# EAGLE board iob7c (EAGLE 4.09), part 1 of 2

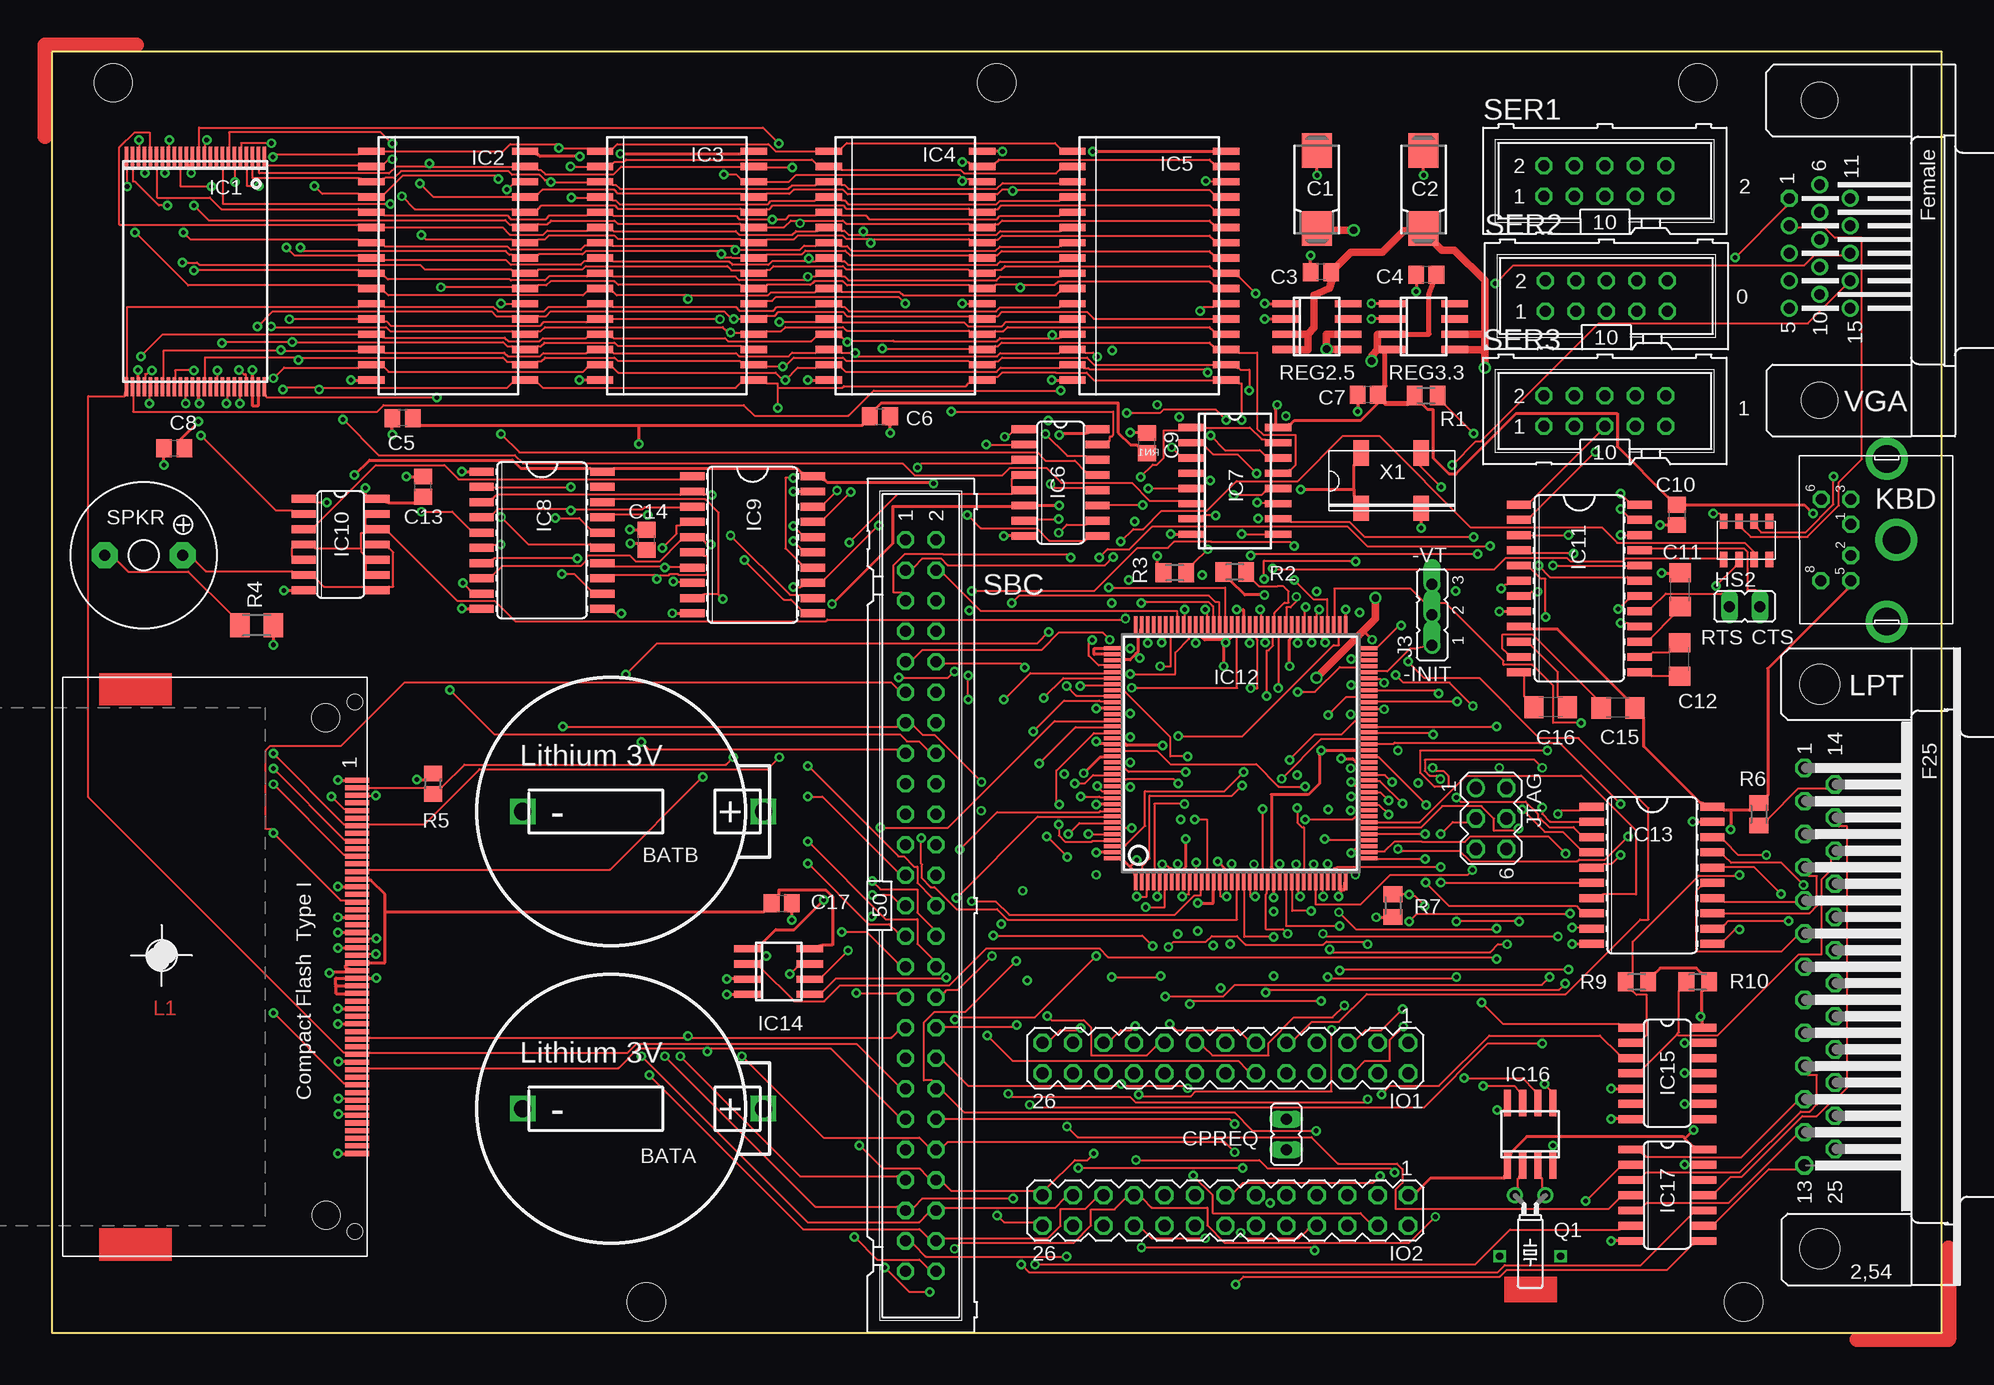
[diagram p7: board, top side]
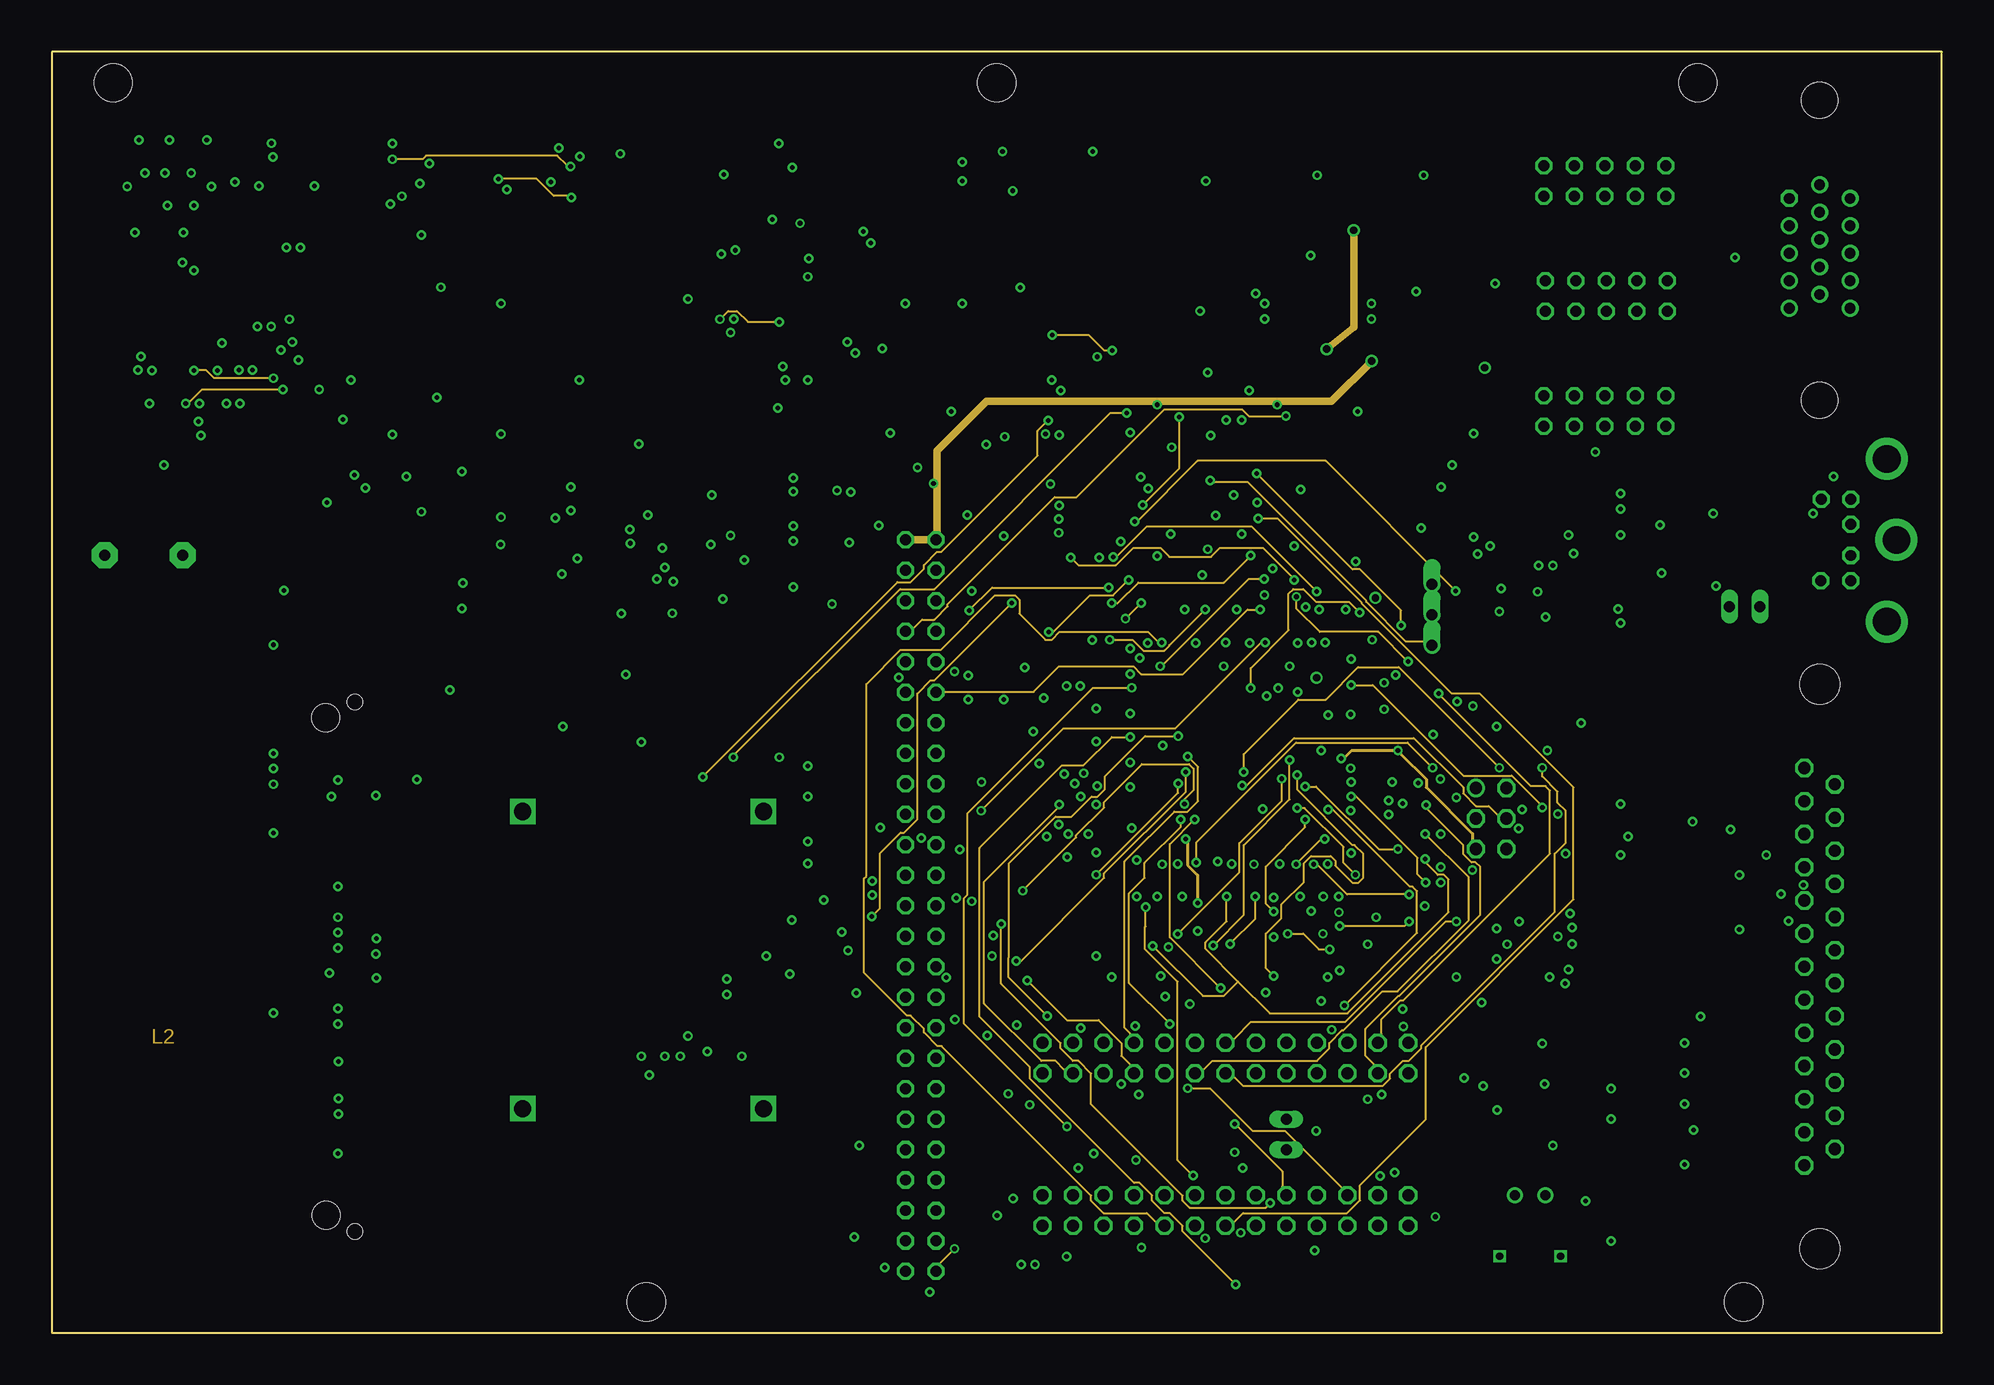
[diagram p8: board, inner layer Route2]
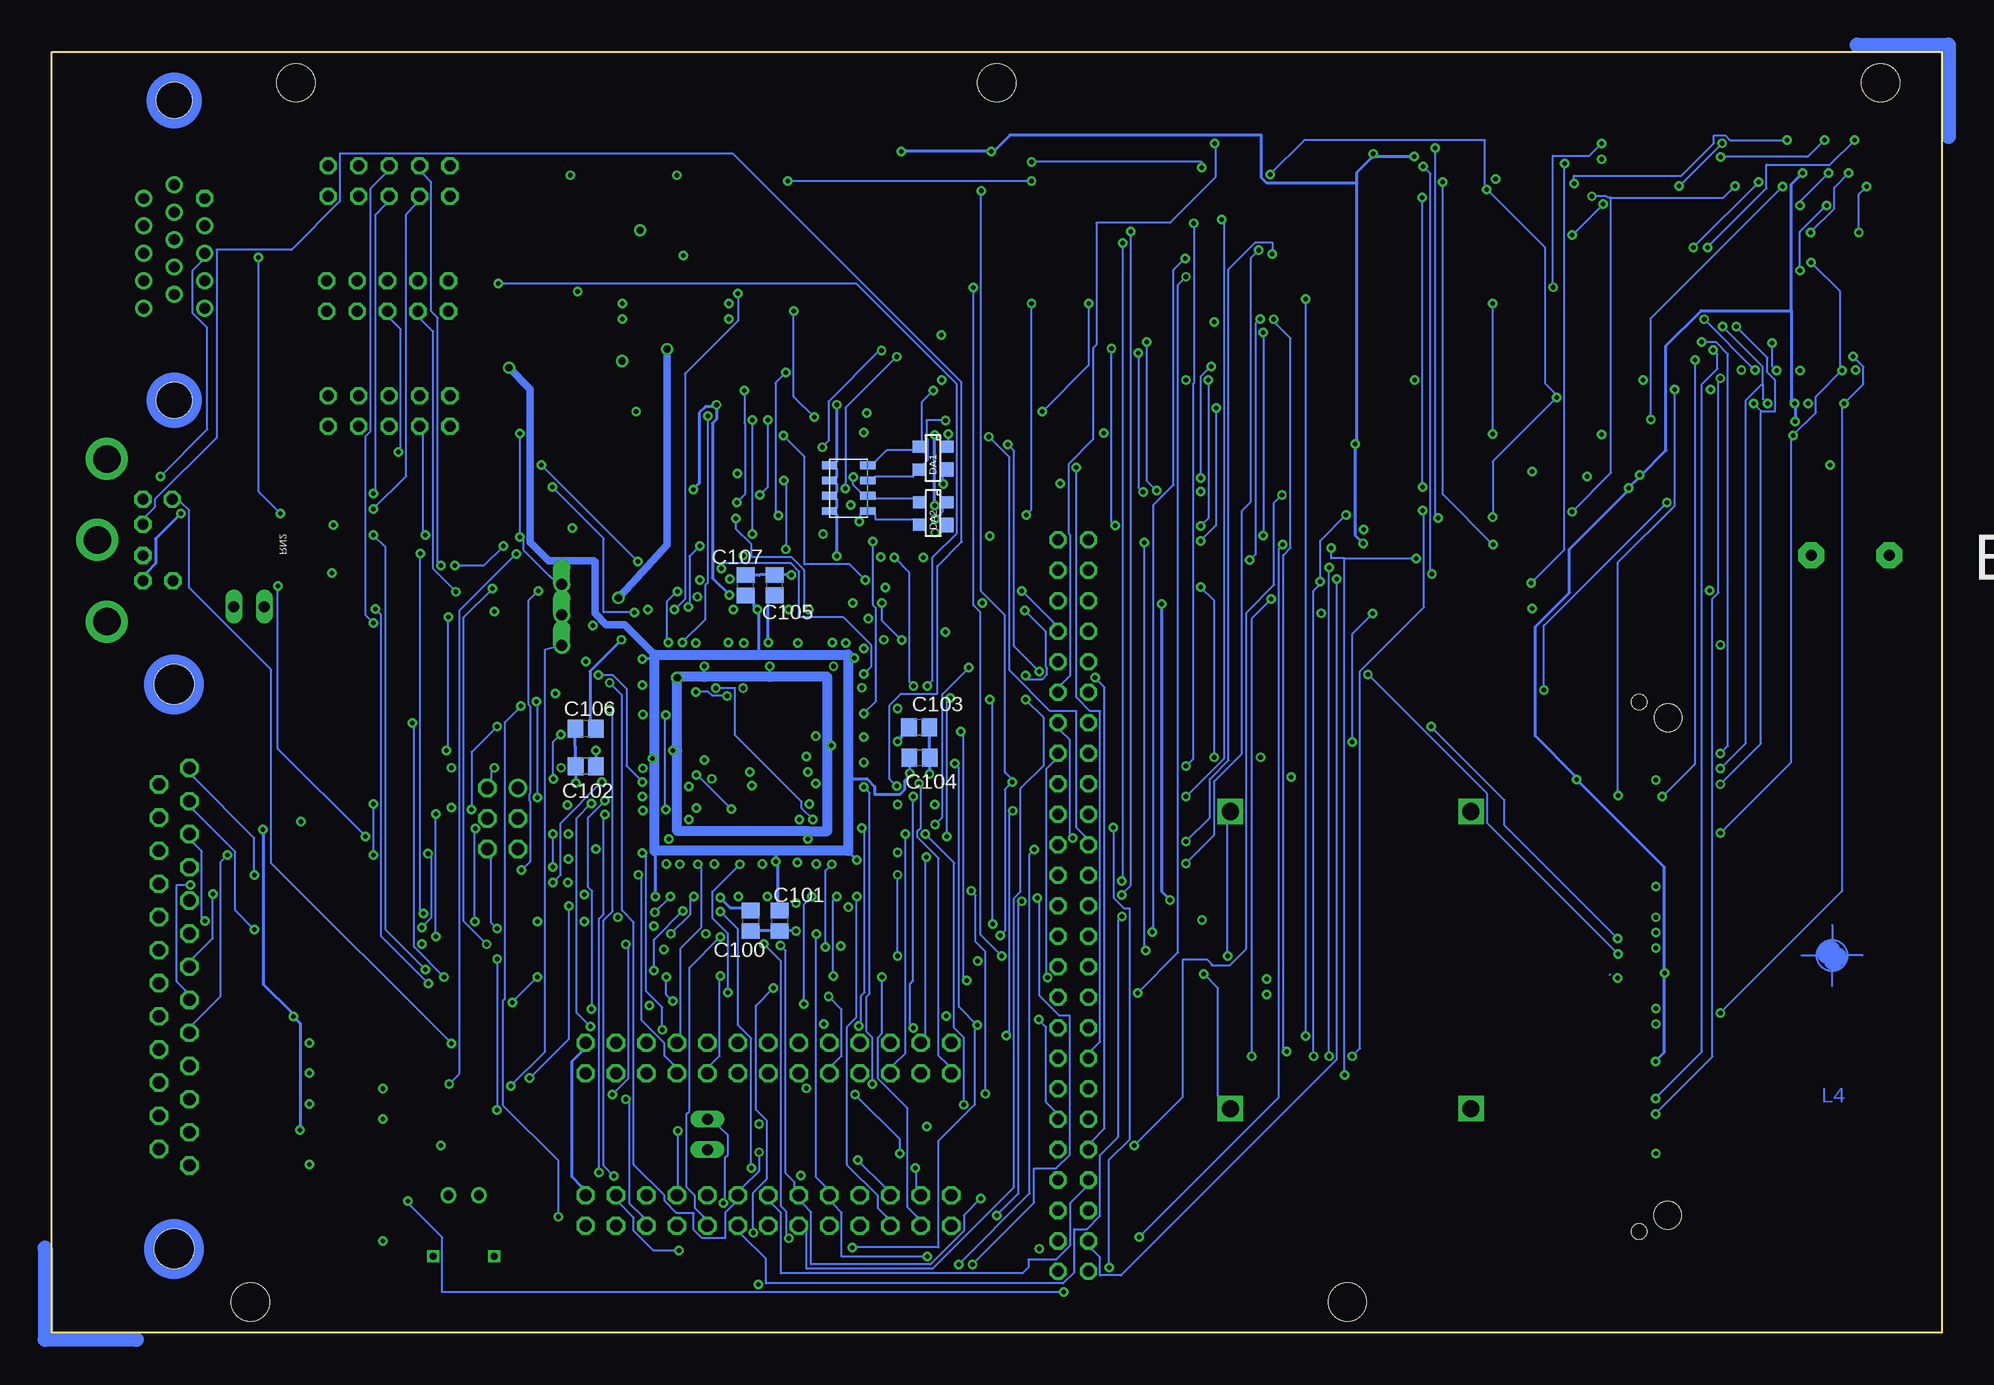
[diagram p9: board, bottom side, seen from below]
Size 157.53 x 106.73 mm. Coordinates in mm from the lower left corner, seen from the top.
Outline: 0,0 157.53,0 157.53,106.73 0,106.73 0,0
Copper layers used: Top, Route2, Bottom
Net classes: 1 power: width 0.254 mm, drill 0.203 mm, clearance 0.381 mm; 2 gnd: width 0.254 mm, clearance 0.381 mm; 3 power2: width 0.254 mm, clearance 0.381 mm
Holes 3.17 mm at 78.77,104.17 141,2.57 5.11,104.17 49.56,2.57 137.19,104.17

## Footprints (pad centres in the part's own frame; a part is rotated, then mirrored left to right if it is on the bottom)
CR2032HOLDER = drill 1.422 square: + 12.7,0; - -7.366,0
085CS_1AR = smd 2.9 x 2.5: + 3.25,0; - -3.25,0
C0805 = smd 1.3 x 1.5: 1 -0.85,0; 2 0.85,0
C1206 = smd 1.6 x 1.8: 1 -1.4,0; 2 1.4,0
CF_SOCKET2_SMT = smd 0.42 x 2: 1 15.545,-17.805; 2 14.275,-17.805; 3 13.005,-17.805; 4 11.735,-17.805; 5 10.465,-17.805; 6 9.195,-17.805; 7 7.925,-17.805; 8 6.655,-17.805; 9 5.385,-17.805; 10 4.115,-17.805; 11 2.845,-17.805; 12 1.575,-17.805; 13 0.305,-17.805; 14 -0.965,-17.805; 15 -2.235,-17.805; 16 -3.505,-17.805; 17 -4.775,-17.805; 18 -6.045,-17.805; 19 -7.315,-17.805; 20 -8.585,-17.805; 21 -9.855,-17.805; 22 -11.125,-17.805; 23 -12.395,-17.805; 24 -13.665,-17.805; 25 -14.935,-17.805; 26 14.91,-17.805; 27 13.64,-17.805; 28 12.37,-17.805; 29 11.1,-17.805; 30 9.83,-17.805; 31 8.56,-17.805; 32 7.29,-17.805; 33 6.02,-17.805; 34 4.75,-17.805; 35 3.48,-17.805; 36 2.21,-17.805; 37 0.94,-17.805; 38 -0.33,-17.805; 39 -1.6,-17.805; 40 -2.87,-17.805; 41 -4.14,-17.805; 42 -5.41,-17.805; 43 -6.68,-17.805; 44 -7.95,-17.805; 45 -9.22,-17.805; 46 -10.49,-17.805; 47 -11.76,-17.805; 48 -13.03,-17.805; 49 -14.3,-17.805; 50 -15.57,-17.805 | hole 2.3: 20.747,-15.177; -20.72,-15.208 | hole 1.27: -22.062,-17.6; 22.048,-17.6
JP1 = drill 0.914 long: 1 0,-1.27; 2 0,1.27
MINI-TYPE-4P = smd 1 x 1: 1 1.2,1; 3 -1.2,-0.9; 4 -1.2,1 | smd 1 x 1.2: 2 1.2,-0.9
TSOP48 = smd 0.3 x 1.6: 1 -6.25,-9.1; 2 -5.75,-9.1; 3 -5.25,-9.1; 4 -4.75,-9.1; 5 -4.25,-9.1; 6 -3.75,-9.1; 7 -3.25,-9.1; 8 -2.75,-9.1; 9 -2.25,-9.1; 10 -1.75,-9.1; 11 -1.25,-9.1; 12 -0.75,-9.1; 13 -0.25,-9.1; 14 0.25,-9.1; 15 0.75,-9.1; 16 1.25,-9.1; 17 1.75,-9.1; 18 2.25,-9.1; 19 2.75,-9.1; 20 3.25,-9.1; 21 3.75,-9.1; 22 4.25,-9.1; 23 4.75,-9.1; 24 5.25,-9.1; 25 5.25,10.1; 26 4.75,10.1; 27 4.25,10.1; 28 3.75,10.1; 29 3.25,10.1; 30 2.75,10.1; 31 2.25,10.1; 32 1.75,10.1; 33 1.25,10.1; 34 0.75,10.1; 35 0.25,10.1; 36 -0.25,10.1; 37 -0.75,10.1; 38 -1.25,10.1; 39 -1.75,10.1; 40 -2.25,10.1; 41 -2.75,10.1; 42 -3.25,10.1; 43 -3.75,10.1; 44 -4.25,10.1; 45 -4.75,10.1; 46 -5.25,10.1; 47 -5.75,10.1; 48 -6.25,10.1
SOP32 = smd 0.6 x 2.2: 1 -9.525,-6.4; 2 -8.255,-6.4; 3 -6.985,-6.4; 4 -5.715,-6.4; 5 -4.445,-6.4; 6 -3.175,-6.4; 7 -1.905,-6.4; 8 -0.635,-6.4; 9 0.635,-6.4; 10 1.905,-6.4; 11 3.175,-6.4; 12 4.445,-6.4; 13 5.715,-6.4; 14 6.985,-6.4; 15 8.255,-6.4; 16 9.525,-6.4; 17 9.525,6.4; 18 8.255,6.4; 19 6.985,6.4; 20 5.715,6.4; 21 4.445,6.4; 22 3.175,6.4; 23 1.905,6.4; 24 0.635,6.4; 25 -0.635,6.4; 26 -1.905,6.4; 27 -3.175,6.4; 28 -4.445,6.4; 29 -5.715,6.4; 30 -6.985,6.4; 31 -8.255,6.4; 32 -9.525,6.4
SO16 = smd 0.66 x 2.032: 1 -4.445,-3.073; 2 -3.175,-3.073; 3 -1.905,-3.073; 4 -0.635,-3.073; 5 0.635,-3.073; 6 1.905,-3.073; 7 3.175,-3.073; 8 4.445,-3.073; 9 4.445,3.073; 10 3.175,3.073; 11 1.905,3.073; 12 0.635,3.073; 13 -0.635,3.073; 14 -1.905,3.073; 15 -3.175,3.073; 16 -4.445,3.073
SOP16 = smd 0.6 x 2.2: 1 -4.445,-3.6; 2 -3.175,-3.6; 3 -1.905,-3.6; 4 -0.635,-3.6; 5 0.635,-3.6; 6 1.905,-3.6; 7 3.175,-3.6; 8 4.445,-3.6; 9 4.445,3.6; 10 3.175,3.6; 11 1.905,3.6; 12 0.635,3.6; 13 -0.635,3.6; 14 -1.905,3.6; 15 -3.175,3.6; 16 -4.445,3.6
SO20W = smd 0.66 x 2.032: 1 -5.715,-5.029; 2 -4.445,-5.029; 3 -3.175,-5.029; 4 -1.905,-5.029; 5 -0.635,-5.029; 6 0.635,-5.029; 7 1.905,-5.029; 8 3.175,-5.029; 9 4.445,-5.029; 10 5.715,-5.029; 11 5.715,5.029; 12 4.445,5.029; 13 3.175,5.029; 14 1.905,5.029; 15 0.635,5.029; 16 -0.635,5.029; 17 -1.905,5.029; 18 -3.175,5.029; 19 -4.445,5.029; 20 -5.715,5.029
SO14 = smd 0.66 x 2.032: 1 -3.81,-3.073; 2 -2.54,-3.073; 3 -1.27,-3.073; 4 0,-3.073; 5 1.27,-3.073; 6 2.54,-3.073; 7 3.81,-3.073; 8 3.81,3.073; 9 2.54,3.073; 10 1.27,3.073; 11 0,3.073; 12 -1.27,3.073; 13 -2.54,3.073; 14 -3.81,3.073
SO24L = smd 0.66 x 2.032: 1 -6.985,-5.029; 2 -5.715,-5.029; 3 -4.445,-5.029; 4 -3.175,-5.029; 5 -1.905,-5.029; 6 -0.635,-5.029; 7 0.635,-5.029; 8 1.905,-5.029; 9 3.175,-5.029; 10 4.445,-5.029; 11 5.715,-5.029; 12 6.985,-5.029; 13 6.985,5.029; 14 5.715,5.029; 15 4.445,5.029; 16 3.175,5.029; 17 1.905,5.029; 18 0.635,5.029; 19 -0.635,5.029; 20 -1.905,5.029; 21 -3.175,5.029; 22 -4.445,5.029; 23 -5.715,5.029; 24 -6.985,5.029
TQFP144 = smd 0.3 x 1.6: 1 -8.75,-10.6; 2 -8.25,-10.6; 3 -7.75,-10.6; 4 -7.25,-10.6; 5 -6.75,-10.6; 6 -6.25,-10.6; 7 -5.75,-10.6; 8 -5.25,-10.6; 9 -4.75,-10.6; 10 -4.25,-10.6; 11 -3.75,-10.6; 12 -3.25,-10.6; 13 -2.75,-10.6; 14 -2.25,-10.6; 15 -1.75,-10.6; 16 -1.25,-10.6; 17 -0.75,-10.6; 18 -0.25,-10.6; 19 0.25,-10.6; 20 0.75,-10.6; 21 1.25,-10.6; 22 1.75,-10.6; 23 2.25,-10.6; 24 2.75,-10.6; 25 3.25,-10.6; 26 3.75,-10.6; 27 4.25,-10.6; 28 4.75,-10.6; 29 5.25,-10.6; 30 5.75,-10.6; 31 6.25,-10.6; 32 6.75,-10.6; 33 7.25,-10.6; 34 7.75,-10.6; 35 8.25,-10.6; 36 8.75,-10.6; 73 8.75,10.6; 74 8.25,10.6; 75 7.75,10.6; 76 7.25,10.6; 77 6.75,10.6; 78 6.25,10.6; 79 5.75,10.6; 80 5.25,10.6; 81 4.75,10.6; 82 4.25,10.6; 83 3.75,10.6; 84 3.25,10.6; 85 2.75,10.6; 86 2.25,10.6; 87 1.75,10.6; 88 1.25,10.6; 89 0.75,10.6; 90 0.25,10.6; 91 -0.25,10.6; 92 -0.75,10.6; 93 -1.25,10.6; 94 -1.75,10.6; 95 -2.25,10.6; 96 -2.75,10.6; 97 -3.25,10.6; 98 -3.75,10.6; 99 -4.25,10.6; 100 -4.75,10.6; 101 -5.25,10.6; 102 -5.75,10.6; 103 -6.25,10.6; 104 -6.75,10.6; 105 -7.25,10.6; 106 -7.75,10.6; 107 -8.25,10.6; 108 -8.75,10.6 | smd 1.6 x 0.3: 37 10.6,-8.75; 38 10.6,-8.25; 39 10.6,-7.75; 40 10.6,-7.25; 41 10.6,-6.75; 42 10.6,-6.25; 43 10.6,-5.75; 44 10.6,-5.25; 45 10.6,-4.75; 46 10.6,-4.25; 47 10.6,-3.75; 48 10.6,-3.25; 49 10.6,-2.75; 50 10.6,-2.25; 51 10.6,-1.75; 52 10.6,-1.25; 53 10.6,-0.75; 54 10.6,-0.25; 55 10.6,0.25; 56 10.6,0.75; 57 10.6,1.25; 58 10.6,1.75; 59 10.6,2.25; 60 10.6,2.75; 61 10.6,3.25; 62 10.6,3.75; 63 10.6,4.25; 64 10.6,4.75; 65 10.6,5.25; 66 10.6,5.75; 67 10.6,6.25; 68 10.6,6.75; 69 10.6,7.25; 70 10.6,7.75; 71 10.6,8.25; 72 10.6,8.75; 109 -10.6,8.75; 110 -10.6,8.25; 111 -10.6,7.75; 112 -10.6,7.25; 113 -10.6,6.75; 114 -10.6,6.25; 115 -10.6,5.75; 116 -10.6,5.25; 117 -10.6,4.75; 118 -10.6,4.25; 119 -10.6,3.75; 120 -10.6,3.25; 121 -10.6,2.75; 122 -10.6,2.25; 123 -10.6,1.75; 124 -10.6,1.25; 125 -10.6,0.75; 126 -10.6,0.25; 127 -10.6,-0.25; 128 -10.6,-0.75; 129 -10.6,-1.25; 130 -10.6,-1.75; 131 -10.6,-2.25; 132 -10.6,-2.75; 133 -10.6,-3.25; 134 -10.6,-3.75; 135 -10.6,-4.25; 136 -10.6,-4.75; 137 -10.6,-5.25; 138 -10.6,-5.75; 139 -10.6,-6.25; 140 -10.6,-6.75; 141 -10.6,-7.25; 142 -10.6,-7.75; 143 -10.6,-8.25; 144 -10.6,-8.75
SO08 = smd 0.6 x 2.2: 1 -1.905,-2.6; 2 -0.635,-2.6; 3 0.635,-2.6; 4 1.905,-2.6; 5 1.905,2.6; 6 0.635,2.6; 7 -0.635,2.6; 8 -1.905,2.6
MA13-2 = drill 1.016 octagon: 1 -15.24,-1.27; 2 -15.24,1.27; 3 -12.7,-1.27; 4 -12.7,1.27; 5 -10.16,-1.27; 6 -10.16,1.27; 7 -7.62,-1.27; 8 -7.62,1.27; 9 -5.08,-1.27; 10 -5.08,1.27; 11 -2.54,-1.27; 12 -2.54,1.27; 13 0,-1.27; 14 0,1.27; 15 2.54,-1.27; 16 2.54,1.27; 17 5.08,-1.27; 18 5.08,1.27; 19 7.62,-1.27; 20 7.62,1.27; 21 10.16,-1.27; 22 10.16,1.27; 23 12.7,-1.27; 24 12.7,1.27; 25 15.24,-1.27; 26 15.24,1.27
JP2 = drill 0.914 offset: 1 -2.54,0; 2 0,0; 3 2.54,0
MA03-2 = drill 1.016 round: 1 -2.54,-1.27 | drill 1.016 octagon: 2 -2.54,1.27; 3 0,-1.27; 4 0,1.27; 5 2.54,-1.27; 6 2.54,1.27
M_DIN6 = drill 0.9 pad 1.422 octagon: 1 -1.3,-3.75; 2 1.3,-3.75; 3 -3.4,-3.75; 5 3.4,-3.75; 6 -3.4,-6.2; 8 3.4,-6.25 | drill 2.3 pad 3.5 round: SH1 6.8,-0.75; SH2 0,0.05; SH3 -6.75,-0.75
F25H = drill 1.016 octagon: 1 -16.561,-1.27; 2 -13.792,-1.27; 3 -11.049,-1.27; 4 -8.28,-1.27; 5 -5.512,-1.27; 6 -2.769,-1.27; 7 0,-1.27; 8 2.769,-1.27; 9 5.512,-1.27; 10 8.28,-1.27; 11 11.049,-1.27; 12 13.792,-1.27; 13 16.561,-1.27; 14 -15.189,1.27; 15 -12.421,1.27; 16 -9.652,1.27; 17 -6.909,1.27; 18 -4.14,1.27; 19 -1.372,1.27; 20 1.372,1.27; 21 4.14,1.27; 22 6.909,1.27; 23 9.652,1.27; 24 12.421,1.27; 25 15.189,1.27 | hole 3.302: -23.52,0; 23.52,0
TC26H = drill 0.813 round: 1 -1.27,0; 2 1.27,0
M0805 = smd 1.3 x 1.6: 1 -0.95,0; 2 0.95,0
M1206 = smd 1.6 x 2: 1 -1.4,0; 2 1.4,0
R0805 = smd 1.3 x 1.5: 1 -0.85,0; 2 0.85,0
RN-CTS-744C043 = smd 0.635 x 1.27: 1 -1.905,-1.905; 2 -0.635,-1.905; 3 0.635,-1.905; 4 1.905,-1.905; 5 1.905,1.27; 6 0.635,1.27; 7 -0.635,1.27; 8 -1.905,1.27
ML50 = drill 0.914 octagon: 1 -30.48,-1.27; 2 -30.48,1.27; 3 -27.94,-1.27; 4 -27.94,1.27; 5 -25.4,-1.27; 6 -25.4,1.27; 7 -22.86,-1.27; 8 -22.86,1.27; 9 -20.32,-1.27; 10 -20.32,1.27; 11 -17.78,-1.27; 12 -17.78,1.27; 13 -15.24,-1.27; 14 -15.24,1.27; 15 -12.7,-1.27; 16 -12.7,1.27; 17 -10.16,-1.27; 18 -10.16,1.27; 19 -7.62,-1.27; 20 -7.62,1.27; 21 -5.08,-1.27; 22 -5.08,1.27; 23 -2.54,-1.27; 24 -2.54,1.27; 25 0,-1.27; 26 0,1.27; 27 2.54,-1.27; 28 2.54,1.27; 29 5.08,-1.27; 30 5.08,1.27; 31 7.62,-1.27; 32 7.62,1.27; 33 10.16,-1.27; 34 10.16,1.27; 35 12.7,-1.27; 36 12.7,1.27; 37 15.24,-1.27; 38 15.24,1.27; 39 17.78,-1.27; 40 17.78,1.27; 41 20.32,-1.27; 42 20.32,1.27; 43 22.86,-1.27; 44 22.86,1.27; 45 25.4,-1.27; 46 25.4,1.27; 47 27.94,-1.27; 48 27.94,1.27; 49 30.48,-1.27; 50 30.48,1.27
ML10 = drill 0.914 octagon: 1 -5.08,-1.27; 2 -5.08,1.27; 3 -2.54,-1.27; 4 -2.54,1.27; 5 0,-1.27; 6 0,1.27; 7 2.54,-1.27; 8 2.54,1.27; 9 5.08,-1.27; 10 5.08,1.27
KSS1201 = drill 0.914 pad 2.159 octagon: + 3.251,0; - -3.251,0
HDF15H = drill 0.9 octagon: 1 4.329,2.54 | drill 0.9 round: 2 2.043,2.54; 3 -0.243,2.54; 4 -2.529,2.54; 5 -4.815,2.54; 6 5.472,0; 7 3.186,0; 8 0.9,0; 9 -1.386,0; 10 -3.672,0; 11 4.329,-2.54; 12 2.043,-2.54; 13 -0.243,-2.54; 14 -2.529,-2.54; 15 -4.815,-2.54 | hole 3: -12.5,0; 12.5,0
SG636 = smd 1.3 x 2.1: P$1 0,0; P$2 5,0; P$3 5,4.6; P$4 0,4.6

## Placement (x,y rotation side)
BATA  [CR2032HOLDER]  46.61,18.67 0 top
BATB  [CR2032HOLDER]  46.61,43.43 0 top
C1  10u  [085CS_1AR]  105.44,95.28 270 top
C2  10u  [085CS_1AR]  114.33,95.28 270 top
C3  0u1  [C0805]  105.77,88.39 180 top
C4  0u1  [C0805]  114.55,88.16 180 top
C5  0u1  [C0805]  29.24,76.23 180 top
C6  0u1  [C0805]  69.01,76.35 0 top
C7  0u1  [C0805]  109.68,78.16 180 top
C8  0u1  [C0805]  10.19,73.69 180 top
C9  0u1  [C0805]  91.26,74.14 90 top
C10  0u1  [C0805]  135.43,68.15 270 top
C11  [C1206]  135.71,61.93 90 top
C12  [C1206]  135.66,56.11 90 top
C13  0u1  [C0805]  30.94,70.51 90 top
C14  0u1  [C0805]  49.56,66.07 90 top
C15  [C1206]  130.53,52.07 180 top
C16  [C1206]  124.92,52.12 180 top
C17  0u1  [C0805]  60.83,35.79 0 top
C100  0u1  [C0805]  99.29,34.34 270 bottom
C101  0u1  [C0805]  96.88,34.34 270 bottom
C102  0u1  [C0805]  113.03,47.22 180 bottom
C103  0u1  [C0805]  85.24,50.47 0 bottom
C104  0u1  [C0805]  85.22,47.93 0 bottom
C105  0u1  [C0805]  97.28,62.31 90 bottom
C106  0u1  [C0805]  113.06,50.32 180 bottom
C107  0u1  [C0805]  99.72,62.28 90 bottom
CF1  CF_CMM_SOCKET2  [CF_SOCKET2_SMT]  7.65,30.51 90 top
CPREQ  [JP1]  102.9,16.54 0 top
DA1  DUAL-DIODE  [MINI-TYPE-4P]  84.1,72.82 0 bottom
DA2  DUAL-DIODE  [MINI-TYPE-4P]  84.07,68.22 0 bottom
HS2  [JP1]  141.1,60.5 270 top
IC1  LH28F400BVHE-BL  [TSOP48]  11.46,88.93 180 top
IC2  TC554001AF  [SOP32]  33.05,88.93 270 top
IC3  TC554001AF  [SOP32]  52.1,88.93 270 top
IC4  TC554001AF  [SOP32]  71.15,88.93 270 top
IC5  TC554001AF  [SOP32]  91.47,88.93 270 top
IC6  74ACT138D  [SO16]  84.07,70.84 270 top
IC7  74HC367E  [SOP16]  98.6,70.99 270 top
IC8  74ACT373D  [SO20W]  40.84,66.04 270 top
IC9  74ACT245DW  [SO20W]  58.39,65.66 270 top
IC10  74ACT32D  [SO14]  24.05,65.68 270 top
IC11  MAX208ECWG  [SO24L]  127.3,62.03 270 top
IC12  [TQFP144]  99.09,48.29 0 top
IC13  74ACT245DW  [SO20W]  133.38,38.13 270 top
IC14  [SO08]  60.58,30.1 270 top
IC15  74ACT05D  [SO14]  134.65,21.62 270 top
IC16  DS1302  [SO08]  123.22,16.54 0 top
IC17  74ACT04D  [SO14]  134.65,11.46 270 top
IO1  [MA13-2]  97.82,22.89 180 top
IO2  [MA13-2]  97.82,10.19 180 top
J3  [JP2]  115.04,59.82 90 top
JTAG  [MA03-2]  119.96,42.85 270 top
KBD  [M_DIN6]  153.7,66.07 270 top
LPT  [F25H]  147.35,30.51 270 top
Q1  32768  [TC26H]  123.22,11.46 180 top
R1  10K  [M0805]  114.55,78.11 180 top
R2  10K  [M0805]  98.6,63.4 0 top
R3  10K  [M0805]  93.6,63.32 0 top
R4  100  [M1206]  17.07,58.95 0 top
R5  10K  [R0805]  31.78,45.75 90 top
R6  4K7  [M0805]  142.27,43.21 90 top
R7  10K  [M0805]  111.79,35.59 90 top
R9  4K7  [M0805]  132.11,29.24 0 top
R10  4K7  [M0805]  137.19,29.24 0 top
REG2.5  TPS77725D  [SO08]  105.44,83.85 270 top
REG3.3  TPS77733D  [SO08]  114.33,83.85 270 top
RN1  [RN-CTS-744C043]  90.81,70.38 270 bottom
RN2  [RN-CTS-744C043]  141.25,66.34 0 top
SBC  ML50E  [ML50]  72.42,35.59 270 top
SER1  [ML10]  129.44,95.99 0 top
SER2  [ML10]  129.57,86.39 0 top
SER3  [ML10]  129.44,76.81 0 top
SPKR  KSS1201  [KSS1201]  7.65,64.8 0 top
U$34  [PASS-ROUND]  9.14,31.45 0 top
U$42  [ANGLE-ARROW-NW1-16]  0.08,106.65 0 top
U$43  [ANGLE-ARROW-SE1-16]  157.45,0.08 0 top
VGA  [HDF15H]  147.35,90.2 90 top
X1  29.4912MHz  [SG636]  109.14,68.71 0 top

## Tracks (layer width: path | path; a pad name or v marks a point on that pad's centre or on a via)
2V5  (via drill 0.38, 0.61)
  Top 0.254: 97.83,57.75 98.09,57.75 98.32,57.98 98.32,58.09 IC12.92 | 97.83,57.75 96.08,57.75 95.89,57.94 95.85,57.94 95.85,58.09 IC12.97 | 97.83,57.75 v97.83,57.52 97.68,57.18 v97.68,55.54 | v101.83,36.26 101.83,36.91 IC12.24 101.79,38.47 101.79,38.66 101.64,38.81 101.64,44.83 104.72,44.83 105.64,45.75 105.64,48.18 v105.79,48.53 108.92,48.53 IC12.55 | v87.05,49.25 87.24,49.06 87.69,49.06 IC12.125 89.26,49.02 89.52,49.02 89.6,48.95 v92.57,48.95 | v94.51,41.14 94.51,38.81 94.36,38.66 94.36,38.47 IC12.9 | v95.5,35.8 96.8,35.8 96.8,36.91 IC12.14 | v103.16,55.54 103.16,57.75 103.31,57.9 103.31,58.09 IC12.82 | v110.06,57.75 109.52,58.28 109.32,58.49
  Top 0.61: v106.25,81.97 106.22,81.94 | v110.31,61.24 110.31,59.49 109.32,58.49 v105.41,54.58 | 106.22,81.94 REG2.5.5 | 106.22,81.94 106.22,83.21 REG2.5.6 | C1.+ 105.59,91.87 v108.51,91.87
  Route2 0.254: v95.5,35.8 95.5,38.13 94.67,38.96 94.67,40.79 v94.51,41.14
  Route2 0.61: v108.51,91.87 108.51,83.77 106.22,81.94 v106.25,81.97
  Bottom 0.254: v97.83,57.52 97.83,60.83 C105.1 | v101.83,36.26 100.99,35.42 100.04,35.42 C100.1 | v87.05,49.25 86.7,49.59 86.7,49.75 C103.1 | v94.51,41.14 94.51,41.81 | 105.41,48.53 v105.79,48.53 | 103.16,54.66 v103.16,55.54 | v110.06,57.75 112.69,55.12 112.69,51.04 C106.1 | 92.89,48.95 v92.57,48.95 | 97.68,54.66 v97.68,55.54
  Bottom 0.61: v106.25,81.97 106.25,65.66 108.74,62.92 109.19,62.41 v110.31,61.24
  Bottom 0.813: v105.41,54.58 105.41,48.53 105.41,41.81 94.51,41.81 92.89,41.81 92.89,48.95 92.89,54.66 97.68,54.66 103.16,54.66 105.54,54.66
5V  (via drill 0.38)
  Top 0.254: C13.1 30.2,69.18 28.11,69.18 IC10.14 26.12,69.79 v26.12,70.4 | 11.57,97.26 11.34,97.26 IC1.14 | 11.57,97.26 IC1.13 | v12.29,77.44 12.22,77.44 12.22,78.05 IC1.37 | v12.22,75.92 10.73,74.43 C8.1 | v11.61,96.65 11.61,97.14 11.57,97.26 | IC14.8 64.22,32.3 65.06,32.3 65.06,36.33 64.49,36.91 60.6,36.91 60.6,36.53 C17.1 59.35,35.08 27.76,35.08 | v23.88,22.62 24.49,22.62 CF1.44 | v23.11,29.97 23.23,30.09 24.49,30.09 CF1.38 24.49,30.35 24.49,30.62 CF1.13 26.43,30.85 27.76,30.85 27.76,35.08 | 27.76,35.08 27.76,36.53 26.58,37.71 26.43,37.71 CF1.32 | v30.43,46.09 31.04,46.09 R5.2 | 137.53,26.35 137.53,28.45 R10.2 137.49,29.97 137.07,30.39 134.06,30.39 133.68,30.01 R9.2 | 137.53,26.35 137.53,25.74 IC15.14 | 136.12,16.18 135.97,16.33 122.94,16.33 121.6,15 IC16.1 121.03,12.87 114.9,12.87 113.79,11.76 IO2.1 | 136.12,16.18 136.73,15.57 IC17.14 | v137.41,26.35 137.53,26.35 | v136.84,16.9 136.12,16.18 | v146.79,68.26 146.06,68.99 136.16,68.99 C10.1 134.71,69.63 130.48,73.86 130.48,76.61 122.06,76.61 117.03,71.58 116.46,71.58 115.13,72.91 115.13,76.95 114.67,76.95 114.25,77.37 R1.2 112.99,77.44 | 139.93,43.54 141.49,43.54 R6.2 143.01,44.79 143.01,55.35 149.64,61.98 KBD.5 | 139.93,43.54 139.4,43.54 IC13.20 137.41,44.15 132.69,48.87 132.69,51.19 C15.1 131.17,52.95 125.49,58.62 123.28,58.62 IC11.9 | 139.93,43.54 v139.93,41.94 | 112.8,83.22 REG3.3.3 110.4,83.21 110.43,81.98 REG3.3.4 111.13,81.67 | C7.1 110.48,77.41 109.11,76.04 103.58,76.04 103.28,75.73 IC7.16 101.98,75.73 101.98,76.99 v102.13,77.33 | v92.11,64.72 92.11,64.11 R3.1 | 108.53,70.28 108.53,72.26 X1.P$4 | 108.53,70.28 108.53,69.75 X1.P$1
  Top 0.254: v101.07,61.48 99.43,61.48 98.29,62.62 R2.1 | v104.08,70.28 108.53,70.28 | v73.48,70.78 73.37,70.89 64.6,70.89 64.41,71.08 IC9.20 62.43,71.69 62.09,72.03 46.85,72.03 IC8.20 44.87,72.03 39.08,72.03 38.39,72.72 26.47,72.72 v25.21,71.46
  Top 0.406: 112.8,83.22 114.78,83.22 114.78,86.54 C4.1 | 112.99,77.44 111.16,77.44 C7.1 111.13,78.89 111.13,81.67
  Route2 0.254: 102.13,77.62 v102.13,77.33 | SBC.2 73.63,65.75 73.76,66.01 | 92.11,77.62 v92.11,77.33 | v73.48,70.78 73.76,70.78
  Route2 0.61: SBC.1 SBC.2 73.74,66.07 73.74,66.12 | 73.76,66.01 73.76,70.78 73.76,73.48 77.9,77.62 92.11,77.62 102.13,77.62 106.65,77.62 110.01,80.98
  Bottom 0.254: v12.22,75.92 12.22,77.37 v12.29,77.44 12.56,77.67 12.56,85.18 | v11.61,96.65 12.56,95.69 12.56,85.18 | 25.13,71.39 23,73.52 23,82.25 20.07,85.18 12.56,85.18 | 25.13,71.39 v26.12,70.4 26.28,70.05 31.04,65.29 31.04,61.67 33.9,58.81 33.9,49.75 30.58,46.43 v30.43,46.09 23.11,38.77 v23.11,29.97 23.11,23.38 v23.88,22.62 | IO1.1 113.37,23.42 114.17,22.62 114.17,12.98 113.37,12.18 IO2.1 | v136.84,16.9 136.84,25.78 v137.41,26.35 137.57,26.7 139.93,29.06 v139.93,41.94 | v146.79,68.26 148.88,66.17 148.88,64.11 149.64,63.35 KBD.5 | v92.11,64.72 92.11,68.19 RN1.4 92.11,68.76 92.11,69.44 RN1.3 92.11,70.05 92.11,70.74 RN1.2 92.11,71.31 92.11,72 RN1.1 92.11,72.57 v92.11,77.33 | v101.07,61.48 102.48,62.89 102.48,75.77 102.13,76.11 v102.13,77.33 102.48,77.18 103.05,77.18 103.58,76.64 103.58,70.78 v104.08,70.28 | 25.13,71.39 v25.21,71.46
B0  (via drill 0.38)
  Top 0.178: v89.87,51.61 89.26,51.61 IC12.120 | v89.1,65.94 90.13,66.97 90.97,66.97 92.49,68.49 96.27,68.49 98.74,70.97 103.85,70.97 107.62,74.74 110.63,74.74 118.25,67.12 129.18,67.12 130.48,65.82 141.11,65.82 141.87,65.06 RN2.3
  Bottom 0.178: v89.87,51.61 88.84,52.64 88.84,60.38 89.1,60.64 v89.1,65.94
C0_L  (via drill 0.38)
  Top 0.178: v104.99,57.52 104.91,57.52 104.91,58.09 IC12.79
  Route2 0.178: v102.86,76.38 99.77,76.38 99.2,76.95 92.72,76.95 85.41,69.63 83.58,69.63 74.66,60.72 74.66,60.53 73.56,59.42 72.53,59.42 71.84,58.74 SBC.7
  Bottom 0.178: v104.99,57.52 103.09,59.42 103.09,62.28 102.9,62.47 102.9,76.34 v102.86,76.38
C1_L  (via drill 0.38)
  Top 0.178: v104.5,60.49 104.38,60.49 104.38,59.65 IC12.80 | v103.54,65.56 103.2,65.9 96.65,65.9 96.61,65.94 93.56,65.94 93.03,65.41 90.47,65.41 86.89,61.82 v76.68,61.82
  Bottom 0.178: v104.5,60.49 104.38,60.6 104.38,64.72 v103.54,65.56 | v76.68,61.82 74.02,59.16 74.02,59.12 SBC.8
CF_DETECT_L  (via drill 0.38)
  Top 0.178: CF1.26 26.43,45.4 31.04,45.4 R5.1 32.52,45.48 34.39,47.35 56.18,47.35 v56.79,47.96 | v98.51,69.82 100.84,69.82 101.1,70.09 IC7.12 | v97.87,76.07 96.99,76.95 92.68,76.95 92.38,76.64 v89.6,76.64
  Route2 0.178: v89.6,76.64 88.23,76.64 73.56,61.98 70.7,61.98 56.79,48.07 v56.79,47.96
  Bottom 0.178: v98.51,69.82 97.87,70.47 v97.87,76.07
CF_L  (via drill 0.38)
  Top 0.178: v83.24,70.74 83.54,70.43 86.17,70.43 IC6.12
  Bottom 0.178: v83.24,70.74 83.24,71.35 DA1.2
CF_READY  (via drill 0.38)
  Top 0.178: v27,31.57 26.43,31.57 CF1.37 | v47.84,54.85 50.43,57.44 82.13,57.44 v83.08,58.39 | v96.57,74.78 97.79,73.56 100.69,73.56 101.1,73.14 IC7.14
  Route2 0.178: v83.08,58.39 83.46,58.39 86.51,61.44 88.46,61.44 v89.75,62.74
  Bottom 0.178: v27,31.57 37.9,42.47 37.9,44.91 v47.84,54.85 | v89.75,62.74 91.05,64.03 94.78,64.03 94.78,72.99 v96.57,74.78
CPUDX0  (via drill 0.38)
  Top 0.178: v82.28,47.42 85.33,50.47 87.69,50.47 IC12.122 | v80.42,25.63 80.23,25.44 74.36,25.44 SBC.34 | v105.26,6.85 104.99,7.11 v90.82,7.11
  Bottom 0.178: v82.28,47.42 81.94,47.08 81.94,27.15 v80.42,25.63 80.57,25.29 80.57,19.04 83.62,15.99 83.62,7.11 v90.82,7.11 | v105.26,6.85 107.39,6.85 109.03,8.48 109.03,9.59 110.17,10.73 IO2.3
CPUDX1  (via drill 0.38)
  Top 0.178: v89.87,45.48 89.26,45.48 IC12.132 | SBC.36 74.36,22.58 76.38,20.56 88.99,20.56 v89.14,20.71 89.48,20.56 94.48,20.56 v94.67,20.37
  Route2 0.178: v94.67,20.37 96.53,20.37 100.08,16.83 102.78,16.83 107.54,12.07 IO2.5
  Bottom 0.178: v89.87,45.48 89.37,44.98 89.37,28.26 89.64,27.99 89.64,25.1 89.14,24.6 v89.14,20.71
CPUDX2  (via drill 0.38)
  Top 0.178: v94.51,46.74 89.75,46.74 89.52,46.96 89.26,46.96 IC12.129 | v80.38,30.96 76.15,26.73 73.56,26.73 72.68,25.86 72.68,21.02 73.37,21.02 SBC.38 74.36,20.03 76.04,18.35 98.55,18.35 100.08,16.83 v105.37,16.83
  Route2 0.178: v94.51,46.74 94.51,45.1 87.69,38.28 87.69,37.9 80.76,30.96 v80.38,30.96
  Bottom 0.178: v105.37,16.83 105.37,12.18 IO2.7
CPUDX3  (via drill 0.38)
  Top 0.178: v93.87,45.78 93.52,46.13 89.6,46.13 89.56,46.09 89.26,46.09 IC12.131 | v87.05,31.38 81.94,26.28 75.46,26.28 v75.27,26.09 | v98.59,17.4 98.17,17.82 74.36,17.82 SBC.40
  Route2 0.178: v93.87,45.78 93.87,44.98 v87.05,38.16 | v98.59,17.4 102.55,13.44 102.55,12.18 IO2.9
  Bottom 0.178: v87.05,31.38 v87.05,38.16 | v75.27,26.09 74.66,25.48 74.66,19.19 73.98,18.5 SBC.40
CPUDX4  (via drill 0.38)
  Top 0.178: 55.58,61.52 55.58,68.34 54.47,69.44 46.85,69.44 IC8.18 | 55.58,61.52 54.36,61.52 IC9.9 | v111.05,54.17 110.74,54.47 110.48,54.47 IC12.67 | v98.59,15.04 97.71,15.91 74.7,15.91 74.36,15.57 SBC.42 72.99,15.57 72.3,16.26 64.3,16.26 v57.52,23.04 | v55.92,61.14 55.61,61.44 55.58,61.52
  Bottom 0.178: v111.05,54.17 110.02,53.14 110.02,35.19 109.03,34.2 109.03,14.01 106.48,11.46 106.48,11 105.45,9.97 104.04,9.97 104.04,8.56 103.35,7.87 101.41,7.87 101.41,10.01 100.69,10.73 IO2.11 99.96,12.1 98.59,13.47 v98.59,15.04 | v55.92,61.14 57.52,59.54 v57.52,23.04
CPUDX5  (via drill 0.38)
  Top 0.178: v49.67,68.15 46.85,68.15 IC8.17 | v51.8,62.59 52.37,62.59 IC9.8 | v111.05,51.96 110.48,51.96 IC12.62 | v110.71,13.06 110.13,12.48 99.28,12.48 98.55,11.76 IO2.13 | v52.37,23.04 62.36,13.06 70.47,13.06 SBC.43
  Bottom 0.178: v49.67,68.15 51.8,66.01 v51.8,62.59 51.96,62.24 52.37,61.82 v52.37,23.04 | v111.05,51.96 110.78,51.69 110.78,35.12 111.54,34.35 111.54,13.89 v110.71,13.06 | SBC.43 71.42,12.03 72.68,10.77 72.68,7.23 73.83,6.08 76.15,6.08 76.15,5.44 76.64,4.94 96.76,4.94 96.76,10.01 97.49,10.73 IO2.13
CPUDX6  (via drill 0.38)
  Top 0.178: 51.08,63.84 52.37,63.84 IC9.7 | 51.08,63.84 46.85,63.84 IC8.14 | v103.16,47.73 105.3,49.86 107.51,49.86 108.61,50.97 108.92,50.97 IC12.60 | v80.11,11.19 72.57,11.19 71.84,10.46 SBC.45 70.47,10.5 63.61,10.5 v51.08,23.04 | v51.08,63.77 51.08,63.84
  Route2 0.178: v103.16,47.73 103.16,44.45 99.35,40.64 99.35,34.81 v96.8,32.26
  Bottom 0.178: v96.8,32.26 96.38,31.84 96.38,13.28 95.62,12.52 95.62,12.18 IO2.15 94.93,10.73 94.25,10.05 94.25,5.7 84.3,5.7 81.52,8.48 81.52,9.78 v80.11,11.19 | v51.08,23.04 v51.08,63.77
CPUDX7  (via drill 0.38)
  Top 0.178: 50.43,63.12 51.42,63.12 51.54,63.23 52.15,63.23 52.22,63.16 54.51,63.16 54.66,63.31 54.66,64.72 54.36,64.72 IC9.6 | 50.43,63.12 46.85,63.12 IC8.13 | v102.51,46.16 105.83,49.48 108.92,49.48 IC12.57 | v84.57,6.35 72.83,6.35 71.84,7.34 SBC.47 | v50.43,62.81 50.43,63.12
  Route2 0.178: v102.51,46.16 102.51,44.34 98.97,40.79 98.97,38.35 v93.83,33.21
  Bottom 0.178: v93.83,33.21 93.83,12.94 93.07,12.18 IO2.17 92.42,10.73 91.69,10.01 91.69,6.35 v84.57,6.35 | v50.43,62.81 50.43,22.77 68.41,4.79 70.17,4.79 70.17,6.27 70.85,6.96 SBC.47
CPUDX8  (via drill 0.38)
  Top 0.178: IC8.8 36.79,63.16 37.52,63.88 44.07,63.88 44.56,64.38 44.56,64.76 48.18,64.76 48.68,64.26 50.66,64.26 52.37,65.98 IC9.5 54.36,65.98 54.66,65.67 v54.93,65.67 | v108.31,45.9 108.61,45.59 108.92,45.59 IC12.49 | v112,54.81 112.65,54.17 116.5,54.17 v118.44,52.22 | v115.32,9.66 113.14,7.49 97.75,7.49 96.3,8.94 96.3,10.43 91.66,10.43 90.93,11.15 IO2.19 89.45,11.15 88.57,10.27 86.63,10.27 86.63,8.94 85.18,7.49 75.73,7.49 v75.23,7 | v66.89,7.99 68.8,6.08 72.3,6.08 72.99,5.4 SBC.50
  Route2 0.178: v75.23,7 74.02,5.78 SBC.50
  Bottom 0.178: v108.31,45.9 109.64,47.23 109.64,53.67 110.78,54.81 v112,54.81 | v118.44,52.22 119.77,50.89 119.77,27.84 119.93,27.69 119.93,18.92 115.32,14.31 v115.32,9.66 | v54.93,65.67 55.27,65.33 55.27,19.61 v66.89,7.99
CPUDX9  (via drill 0.38)
  Top 0.178: v43.8,64.53 36.87,64.53 36.79,64.45 IC8.7 | v50.89,65.41 52.07,66.59 52.07,67.27 52.37,67.27 IC9.4 | v111.43,43.19 110.67,43.95 110.48,43.95 IC12.46 | v111.93,13.36 111.58,13.7 101.33,13.7 100.65,14.39 v90.36,14.39 | IO2.21 86.93,11.11 86.13,10.31 84.07,10.31 84.07,8.9 83.05,7.87 74.36,7.87 SBC.48 72.99,7.95 72.3,8.64 62.62,8.64 v49.78,21.48
  Bottom 0.178: 49.78,64.53 50.89,64.53 v50.89,65.41 | 49.78,64.53 v43.8,64.53 | v111.43,43.19 111.54,43.08 111.54,34.89 111.93,34.51 v111.93,13.36 | v90.36,14.39 88.07,12.1 IO2.21 | v49.78,21.48 49.78,64.53
CPUDX10  (via drill 0.38)
  Top 0.178: 43.27,68.61 49.21,68.61 49.4,68.8 52.37,68.8 IC9.3 | 43.27,68.61 37.13,68.61 36.79,68.26 IC8.4 | v104.46,42.77 108.42,42.77 108.61,42.96 108.92,42.96 IC12.44 | v85.56,13.74 v99.24,13.74 | IO2.23 84.38,11.15 83.65,10.43 74.36,10.43 SBC.46 72.99,9.89 72.3,9.21 62.97,9.21 v49.14,23.04 | v43.27,68.53 43.27,68.61
  Route2 0.178: v104.46,42.77 104.46,42.13 101.18,38.85 101.18,35.76 v101.83,35.12
  Bottom 0.178: v101.83,35.12 100.34,33.63 100.34,25.63 99.24,24.52 v99.24,13.74 | v85.56,13.74 85.45,13.63 85.45,12.18 IO2.23 | v43.27,68.53 43.15,68.41 43.15,60.45 48.49,55.12 48.49,23.69 v49.14,23.04
CPUDX11  (via drill 0.38)
  Top 0.178: IC8.3 36.79,69.52 37.1,69.82 52.37,69.82 IC9.2 54.36,69.82 v55,69.82 | v108.31,39.99 108.8,40.49 108.92,40.49 IC12.39 | v106.67,25.25 106.67,20.1 95.31,20.1 94.93,19.72 90.7,19.72 v90.59,19.84 | v86.86,14.92 86.32,14.39 85.26,14.39 82.97,12.1 IO2.25 81.9,11.84 74.93,11.84 74.36,12.41 SBC.44 72.99,13.02 72.3,13.7 69.22,13.7 v67.31,15.61
  Bottom 0.178: v108.31,39.99 108,39.69 108,28.45 106.67,27.11 v106.67,25.25 | v90.59,19.84 86.86,16.1 v86.86,14.92 | v55,69.82 55.65,69.18 55.65,62.32 57.98,59.99 57.98,31.99 59.35,30.62 60.87,30.62 60.87,30.73 61.25,31.12 63.27,31.12 63.27,19.65 v67.31,15.61
CTS2
  Top 0.178: IC11.17 133.34,60.41 134.52,61.6 139.2,61.6 HS2.1
DA0  (via drill 0.38)
  Top 0.178: v18.31,99.12 15.76,99.12 15.76,98.82 IC1.5 | v21.89,95.54 22.54,94.89 25.55,94.89 IC2.4 27.72,94.89 29.25,96.42 36.94,96.42 v37.21,96.15 | v43.27,70.47 36.79,70.47 IC8.2 | v43.31,94.59 44.6,94.59 IC3.4 46.77,94.36 47,94.36 47.31,94.06 59.69,94.06 59.96,94.32 63.58,94.32 63.65,94.4 IC4.4 65.82,94.36 66.05,94.36 66.36,94.06 78.74,94.06 79.01,94.32 83.96,94.32 84,94.36 IC5.4
  Route2 0.178: v37.21,96.15 40.41,96.15 41.82,94.74 42.96,94.74 v43.31,94.59
  Bottom 0.178: v21.89,95.54 v18.31,99.12 | v43.27,70.47 43.31,70.51 v43.31,94.59
DA1  (via drill 0.38)
  Top 0.178: v17.25,95.54 16.26,95.54 16.26,97.26 IC1.4 | v29.17,94.7 30.24,93.64 38.35,93.64 IC2.28 40.53,93.64 40.83,93.94 46.89,93.94 47.16,93.68 57.37,93.68 57.4,93.64 IC3.28 59.58,93.64 59.8,93.64 60.11,93.94 65.94,93.94 66.21,93.68 76.42,93.68 76.45,93.64 IC4.28 78.63,93.64 78.85,93.64 79.16,93.94 96.49,93.94 96.8,93.64 IC5.28 | v30.81,68.41 33.36,68.41 34.81,66.97 IC8.5
  Bottom 0.178: v17.25,95.54 18.2,94.59 27.57,94.59 | 27.57,94.59 27.84,94.59 27.95,94.7 v29.17,94.7 | v30.81,68.41 27.57,71.65 27.57,94.59
DA2  (via drill 0.38)
  Top 0.178: IC1.3 16.75,97.26 16.75,96.19 25.59,96.19 IC2.3 27.72,96.19 27.76,96.23 28.52,96.23 29.1,96.8 38.05,96.8 38.35,96.49 40.64,96.49 41.1,96.04 41.25,96.04 v41.59,95.89 44.6,95.89 IC3.3 46.77,95.66 47,95.66 47.35,95.31 61.37,95.31 61.67,95.62 63.61,95.62 63.65,95.66 IC4.3 65.82,95.66 66.05,95.66 66.4,95.31 78.74,95.31 79.24,95.81 84,95.81 IC5.3 | v37.4,65.67 36.79,65.67 IC8.6
  Bottom 0.178: v37.4,65.67 41.59,69.86 v41.59,95.89
DA3  (via drill 0.38)
  Top 0.178: IC5.31 96.8,97.45 96.49,97.75 78.93,97.75 78.63,97.45 IC4.31 76.45,97.45 76.34,97.56 v75.88,97.56 | 31.46,97.18 28.68,97.18 28.11,96.61 17.28,96.61 17.28,97.26 IC1.2 | 31.46,97.18 IC2.31 40.53,96.91 40.75,96.91 41.14,96.53 46.81,96.53 47.46,97.18 IC3.31 59.58,97.1 v61.71,97.1 | v34.24,62.47 34.81,61.9 IC8.9 | v31.46,97.45 31.46,97.18
  Bottom 0.178: v34.24,62.47 31.46,65.25 v31.46,97.45 | v75.88,97.56 61.71,97.56 v61.71,97.1
DA4  (via drill 0.38)
  Top 0.178: IC1.1 17.82,97.26 25.55,97.26 IC2.2 27.72,97.45 28.07,97.79 v28.37,97.79 | v42.51,63.23 43.54,63.23 44.87,61.9 IC8.12 | v43.23,97.18 IC3.2 46.77,97.45 46.89,97.56 47.65,97.56 47.84,97.75 63.35,97.75 63.65,97.45 IC4.2 65.82,96.91 75.73,96.91 76.04,96.61 83.69,96.61 84,96.91 IC5.2
  Route2 0.178: v28.37,97.79 30.89,97.79 31.19,98.09 42.13,98.09 42.89,97.33 v43.23,97.18
  Bottom 0.178: v42.51,63.23 42.62,63.35 42.62,96.57 v43.23,97.18
DA5  (via drill 0.38)
  Top 0.178: 75.94,96.17 75.96,96.15 76.45,96.15 IC4.30 | 75.94,96.17 75.62,96.49 62.01,96.49 61.44,95.92 59.58,95.92 IC3.30 57.4,96.15 57.02,96.53 v55.99,96.53 | v96.19,95.96 96.8,95.96 IC5.30 | v75.88,95.96 75.88,96.11 75.94,96.17 | v32.11,77.94 17.93,77.94 17.82,78.05 IC1.48 | v37.44,67.96 39.69,65.71 44.87,65.71 IC8.15 | v37.94,95.28 37.97,95.28 38.35,95.66 IC2.30
  Bottom 0.178: v75.88,95.96 v96.19,95.96 | v37.44,67.96 37.44,72.61 v32.11,77.94 32.26,78.28 33.06,79.08 33.06,90.4 v37.94,95.28 38.09,95.62 38.09,99.39 53.14,99.39 v55.99,96.53
DA6  (via drill 0.38)
  Top 0.178: v9.78,99.39 9.78,98.82 IC1.17 | v18.43,97.98 18.66,98.21 25.55,98.21 IC2.1 27.72,98.44 37.59,98.44 38.2,99.05 42.05,99.05 v42.24,98.74 42.28,98.7 44.6,98.7 IC3.1 46.77,98.7 47.12,99.05 59.73,99.05 60.34,98.44 63.65,98.44 IC4.1 65.82,98.7 66.24,99.12 83.62,99.12 84,98.74 IC5.1 | v41.97,67.88 43.95,67.88 44.87,66.97 IC8.16
  Bottom 0.178: v9.78,99.39 11.19,97.98 v18.43,97.98 | v41.97,67.88 42.24,68.15 v42.24,98.74
DISK_CE_L  (via drill 0.38)
  Top 0.178: v22.92,69.18 21.97,69.18 IC10.1 | v33.17,53.56 36.87,49.86 70.7,49.86 71.27,49.29 72.26,49.29 72.99,48.56 SBC.16 | v74.55,29.59 74.47,29.51 65.33,29.51 64.26,28.45 IC14.5
  Bottom 0.178: v22.92,69.18 33.17,58.93 v33.17,53.56 | v74.55,29.59 74.66,29.71 74.66,46.96 74.02,47.61 SBC.16
DISK_CE_L_NV  (via drill 0.38)
  Top 0.178: IC6.4 80.04,71.16 80.04,70.51 IC6.5 80,69.9 70.51,69.9 v66.47,65.86 | v66.36,31.84 64.26,29.74 IC14.6
  Bottom 0.178: v66.36,31.84 66.47,31.95 v66.47,65.86
DX4  (via drill 0.38)
  Top 0.178: v57.71,64.38 60.99,61.1 61.6,61.1 62.43,60.26 IC9.11 | IC5.21 96.8,84.49 86.86,84.49 86.28,85.06 79.2,85.06 78.85,84.72 78.63,84.72 IC4.21 76.45,84.72 66.28,84.72 65.94,85.06 60.57,85.06 60.26,84.76 59.58,84.76 IC3.21 57.4,84.49 v56.83,84.49 56.49,84.65 56.03,85.1 41.55,85.1 41.17,84.72 40.53,84.72 IC2.21 38.35,84.72 37.02,84.72 36.64,85.1 18.39,85.1 v17.13,83.85 | v15.68,77.44 15.68,78.05 IC1.44 | v18.47,45.71 24.33,39.84 24.49,39.84 CF1.6
  Bottom 0.178: v57.71,64.38 57.21,64.87 57.21,84.11 v56.83,84.49 | 15.04,76.8 v15.68,77.44 | 15.04,76.8 13.89,76.8 13.89,79.39 14.54,80.04 14.54,81.25 v17.13,83.85 | v18.47,45.71 15.08,49.1 15.08,76.72 15.04,76.8
DX5  (via drill 0.38)
  Top 0.178: v56.57,66.43 61.52,61.48 62.43,61.48 IC9.12 | IC5.20 96.8,83.5 96.49,83.81 79.65,83.81 79.31,83.46 78.63,83.46 IC4.20 76.45,83.46 76.42,83.5 66.24,83.5 65.94,83.81 61.14,83.81 60.8,83.46 59.58,83.46 IC3.20 57.4,83.35 v56.57,83.35 56.22,83.5 55.92,83.81 41.1,83.81 40.75,83.46 40.53,83.46 IC2.20 38.35,83.46 28.18,83.46 27.84,83.81 18.31,83.81 v18.28,83.85 | v14.54,77.44 14.66,77.44 14.66,78.05 IC1.42 | v18.47,47 24.37,41.1 24.49,41.1 CF1.5
  Bottom 0.178: v56.57,83.35 v56.57,66.43 | v14.54,77.44 14.92,77.83 14.92,79.04 | 14.92,79.04 14.92,80.49 v18.28,83.85 | v18.47,47 16.33,49.14 16.33,77.71 15,79.04 14.92,79.04
DX6  (via drill 0.38)
  Top 0.178: IC7.13 103.28,71.92 103.66,72.3 103.66,74.82 100.99,74.82 100.46,75.35 100.46,81.67 98.93,81.67 IC5.19 96.8,82.21 96.49,82.51 79.16,82.51 78.85,82.21 78.63,82.21 IC4.19 76.45,82.02 v69.22,82.02 | v68.91,67.27 64.41,62.78 IC9.13 62.43,62.17 62.4,62.13 v61.79,62.13 | v13.78,80.19 13.78,79.62 IC1.40 | v14.16,82.47 14.24,82.55 v20.03,82.55 37.59,82.55 37.94,82.21 38.35,82.21 IC2.19 40.53,82.21 40.75,82.21 41.06,82.51 46.89,82.51 47.16,82.25 57.37,82.25 57.4,82.21 IC3.19 | v18.47,48.26 24.33,42.39 24.49,42.39 CF1.4 26.43,42.39 31.08,42.39 35.65,46.96 59.65,46.96 v60.64,47.96
  Bottom 0.178: v68.91,67.27 69.22,67.58 v69.22,82.02 | v13.78,80.19 14.16,80.57 v14.16,82.47 | v18.47,48.26 17.82,48.91 17.82,81.56 18.81,82.55 v20.03,82.55 | v61.79,62.13 60.64,60.99 v60.64,47.96
DX7  (via drill 0.38)
  Top 0.178: v61.79,71.23 61.14,71.23 61.14,65.37 62.43,64.07 IC9.14 | v100.46,69.18 101.1,69.18 IC7.11 | v99.81,78.51 99.81,80.26 99.05,80.26 98.93,80.38 IC5.18 96.8,80.68 86.86,80.68 86.28,81.25 79.2,81.25 78.89,80.95 78.63,80.95 IC4.18 76.45,80.91 76.38,80.99 66.21,80.99 65.94,81.25 61.82,81.25 61.25,80.68 v60.91,80.53 59.58,80.53 IC3.18 57.4,80.91 57.33,80.99 47.16,80.99 46.89,81.25 41.1,81.25 40.79,80.95 40.53,80.95 IC2.18 38.35,80.91 37.94,80.91 37.59,81.25 20.56,81.25 | 20.56,81.25 12.75,81.25 12.75,79.62 IC1.38 | v23.3,44.68 24.33,43.65 24.49,43.65 CF1.3 | v20.56,81.06 20.56,81.25
  Bottom 0.178: v61.79,71.23 61.79,79.65 v60.91,80.53 | v100.46,69.18 99.77,69.86 99.77,75.77 99.81,75.81 v99.81,78.51 | v23.3,44.68 20.56,47.42 v20.56,81.06
DX8  (via drill 0.38)
  Top 0.178: v61.79,65.98 62.43,65.33 IC9.15 | 60.49,78.74 60.49,79.12 59.58,79.12 IC3.17 57.4,79.16 56.98,78.74 40.91,78.74 40.53,79.12 IC2.17 38.35,79.16 37.94,78.74 22.28,78.74 | 60.49,78.74 v60.49,77.06 | 60.49,78.74 65.86,78.74 66.01,78.89 76.19,78.89 76.45,79.16 IC4.17 78.63,79.65 78.85,79.65 79.24,80.04 83.62,80.04 83.65,80 86.25,80 86.86,79.39 96.8,79.39 IC5.17 98.93,79.12 99.16,79.12 v99.16,76.07 | v99.16,66.55 IC7.9 | v11.15,77.44 11.15,78.05 IC1.35 | v19.27,78.59 19.42,78.74 22.28,78.74 | v27,44.75 26.43,44.75 CF1.2 | v22.28,78.59 22.28,78.74
  Route2 0.178: v11.15,77.44 11.34,77.44 12.48,78.59 v19.27,78.59
  Bottom 0.178: v61.79,65.98 60.49,67.27 v60.49,77.06 | v99.16,76.07 v99.16,66.55 | v27,44.75 27,64.19 22.28,68.91 v22.28,78.59
DX9  (via drill 0.38)
  Top 0.178: v61.79,67.23 62.43,66.59 IC9.16 | v96.99,68.11 96.08,68.11 IC7.7 | v96.34,80.04 96.08,80.3 86.47,80.3 86.4,80.38 86.13,80.38 IC5.15 84,80.42 79.08,80.42 78.74,80.07 66.17,80.07 65.82,80.42 IC4.15 63.65,80.42 62.17,80.42 v61.14,79.39 60.8,79.54 60.34,80 47.19,80 46.77,80.42 IC3.15 44.6,80.42 44.26,80.07 28.07,80.07 27.72,80.42 IC2.15 25.55,80.42 19.34,80.42 v18.47,79.54 | v11.84,80.19 10.27,80.19 10.27,79.62 IC1.33 | v23.88,18.24 24.49,18.24 CF1.23
  Route2 0.178: v11.84,80.19 12.87,80.19 13.51,79.54 v18.47,79.54
  Bottom 0.178: v61.79,67.23 61.14,67.88 v61.14,79.39 | v96.99,68.11 97.22,68.34 97.22,79.16 v96.34,80.04 | v23.88,18.24 19.11,23 19.11,61.18 18.62,61.67 18.62,79.2 v18.47,79.54
DX10  (via drill 0.38)
  Top 0.178: v66.59,70.05 64.41,67.88 IC9.17 | v87.12,81.33 86.78,81.67 86.13,81.67 IC5.14 84,81.67 83.96,81.64 79.04,81.64 78.78,81.37 67.2,81.37 v66.97,81.64 66.93,81.67 65.82,81.67 IC4.14 63.65,81.67 61.71,81.67 61.4,81.37 57.29,81.37 57.02,81.64 46.81,81.64 46.77,81.67 IC3.14 44.6,81.67 44.56,81.64 40.94,81.64 40.68,81.37 38.01,81.37 37.71,81.67 27.72,81.67 IC2.14 25.55,81.83 19.08,81.83 | v91.39,70.36 IC7.5 | 19.08,81.83 9.28,81.83 9.28,79.62 IC1.31 | v23.88,19.53 24.49,19.53 CF1.22 | v19.08,81.9 19.08,81.83
  Bottom 0.178: v66.59,70.05 66.97,70.43 v66.97,81.64 | v91.39,70.36 91.39,77.06 v87.12,81.33 | v23.88,19.53 19.99,23.42 19.99,79.04 18.69,80.34 18.69,81.52 v19.08,81.9
DX11  (via drill 0.38)
  Top 0.178: v65.44,70.17 64.41,69.14 IC9.18 | 83.39,82.89 79.01,82.89 78.74,82.63 70.17,82.63 70.13,82.66 66.62,82.66 v66.28,82.55 65.9,82.93 65.82,82.93 IC4.13 63.65,82.97 63.31,82.63 56.38,82.63 56.11,82.89 46.81,82.89 46.77,82.93 IC3.13 44.6,82.97 44.53,82.89 40.91,82.89 40.64,82.63 38.05,82.63 37.74,82.93 27.72,82.93 IC2.13 25.55,83.2 9.25,83.2 v7.42,81.37 | 83.39,82.89 83.96,82.89 84,82.93 IC5.13 | v93.33,73.79 93.94,73.18 IC7.3 | 83.39,82.89 v83.39,83.16 | v8.14,77.44 8.14,78.05 IC1.29 | v18.47,26.66 24.33,20.79 24.49,20.79 CF1.21
  Route2 0.178: v88.38,81.86 87.69,81.86 86.4,83.16 v83.39,83.16
  Bottom 0.178: v65.44,70.17 66.28,71.01 v66.28,82.55 | v93.33,73.79 92.8,74.32 92.8,77.6 88.53,81.86 v88.38,81.86 | v7.42,81.37 6.54,80.49 6.54,79.04 v8.14,77.44 8.29,77.1 8.29,36.83 v18.47,26.66
EMA0  (via drill 0.38)
  Top 0.178: v72.15,72.11 72.49,72.45 80,72.45 IC6.3
  Bottom 0.178: v72.15,72.11 72.15,52.95 71.01,51.8 70.17,51.8 70.17,24.26 70.85,23.57 SBC.35
EMA1  (via drill 0.38)
  Top 0.178: v75.23,55.12 74.7,54.58 v70.59,54.58 | v77.86,74.02 IC6.2
  Bottom 0.178: v77.86,74.02 77.33,73.48 77.33,57.21 v75.23,55.12 | v70.59,54.58 69.79,53.78 69.79,17.02 70.85,15.95 SBC.41
EMA2  (via drill 0.38)
  Top 0.178: v79.43,74.66 79.65,74.66 80,75.01 IC6.1
  Bottom 0.178: v79.43,74.66 77.71,72.95 77.71,55.19 74.32,51.8 72.15,51.8 72.15,42.09 71.42,41.36 SBC.21
FLASH_L  (via drill 0.38)
  Top 0.178: v82.82,74.89 84.65,73.06 86.17,73.06 IC6.14
  Bottom 0.178: v82.82,74.89 82.82,74.32 DA1.1
FLASH_RDY  (via drill 0.38)
  Top 0.178: v13.28,95.5 10.73,95.5 10.73,97.26 IC1.15 | v24.26,76.11 27.23,73.14 38.58,73.14 39.27,72.45 70.89,72.45 71.88,71.46 79.24,71.46 79.85,72.07 82.89,72.07 84.15,70.82 90.02,70.82 91.5,69.33 93.9,69.33 IC7.6
  Bottom 0.178: v13.28,95.5 24.26,84.53 v24.26,76.11
FPGA_DONE_H  (via drill 0.38)
  Top 0.178: v112.46,58.93 112.27,58.93 110.48,57.14 IC12.72 | v100.42,71.62 98.86,73.18 96.8,73.18 96.08,73.9 IC7.2
  Route2 0.178: v112.46,58.93 112.46,60.19 109.03,63.61 108.42,63.61 v100.42,71.62
FPGA_INIT_L/RTC_CLK  (via drill 0.38)
  Top 0.178: v96.53,71.01 96.42,71.01 96.08,71.35 IC7.4 | v96.34,65.29 95.16,64.11 R3.2 | IC12.68 110.48,55.12 111.32,55.12 113.18,56.98 113.64,56.98 J3.1 | v119.28,20.56 121.91,20.56 122.29,20.18 IC16.7
  Route2 0.178: v96.53,71.01 96.88,70.85 99.7,70.85 109.56,60.99 109.56,60.91 112.88,57.59 114.36,57.59 J3.1
  Bottom 0.178: v96.53,71.01 96.34,70.82 v96.34,65.29 | v119.28,20.56 116.42,23.42 116.42,56.95 J3.1
FPGA_L  (via drill 0.38)
  Top 0.178: v83.92,66.66 84.61,67.35 86.17,67.35 IC6.10
  Bottom 0.178: v83.92,66.66 83.92,66.74 83.35,66.74 DA2.2
FPGA_PROGRAM_L  (via drill 0.38)
  Top 0.178: v103.85,53.4 105.3,53.4 107.35,55.46 108.92,55.46 IC12.69 | v101.26,53.06 101.26,56.87 101.41,56.87 101.79,57.25 101.79,58.09 IC12.85 101.9,59.65 101.9,59.99 102.74,60.83 103.09,60.83 103.09,61.79 102.67,62.2 102.13,62.2 102.1,62.17 100.65,62.17 100.19,62.62 R2.2
  Bottom 0.178: v103.85,53.4 102.82,53.4 102.48,53.06 v101.26,53.06
FPGA_WR_L/RTC_IO  (via drill 0.38)
  Top 0.178: v105.18,39.04 104.91,39.04 104.91,38.47 IC12.30 | R7.2 112.57,36.53 v113.14,36.53 113.49,36.37 113.64,36.37 v114.44,35.57 | v117.72,21.21 122.59,21.21 123.58,20.22 IC16.6
  Route2 0.178: v105.18,39.04 105.45,39.04 107.96,36.53 v113.14,36.53
  Bottom 0.178: v117.72,21.21 114.44,24.49 v114.44,35.57
G0  (via drill 0.38)
  Top 0.178: v104.46,45.52 102.25,45.52 100.38,47.38 93.22,47.38 92.11,48.49 89.26,48.49 IC12.126 | v112.19,40.3 112.31,40.18 117.34,40.18 118.25,39.27 127.13,39.27 127.28,39.42 129.45,39.42 v131.39,41.36 | v138.71,62.24 140.31,63.84 RN2.2
  Route2 0.178: v104.46,45.52 105.37,45.52 110.59,40.3 v112.19,40.3
  Bottom 0.178: v131.39,41.36 138.71,48.68 v138.71,62.24
GND  (via drill 0.38)
  Top 0.254: 23.69,28.91 23.65,28.87 23.65,28.3 23.69,28.26 24.49,28.26 CF1.15 | 23.69,28.91 CF1.39 | 23.69,28.91 23.65,29.02 23.65,29.51 23.69,29.55 24.49,29.55 CF1.14 26.43,29.55 v27.04,29.55 | IC12.110 87.69,56.53 86.89,56.53 86.86,56.57 86.86,56.98 86.89,57.02 87.69,57.02 IC12.109 89.26,57.02 v89.87,57.02 | IC1.47 17.21,78.05 17.21,77.25 17.17,77.22 16.75,77.22 16.71,77.25 16.71,78.05 IC1.46 16.71,79.62 v16.71,80.23 | v7.19,80.23 7.19,79.62 IC1.27 | v87.05,40.03 87.69,40.03 IC12.143 | v93.83,39.08 93.83,38.47 IC12.8 | v87.05,44.03 87.69,44.03 IC12.135 | v89.87,47.54 89.26,47.54 IC12.128 | v98.32,39.08 98.32,38.47 IC12.17 | v87.05,52.03 87.69,52.03 IC12.119 | v102.32,39.08 102.32,38.47 IC12.25 | v106.32,39.08 106.32,38.47 IC12.33 | v91.35,57.48 91.35,58.09 IC12.106 | v95.35,57.48 95.35,58.09 IC12.98 | v108.27,43.54 108.92,43.54 IC12.45 | v108.27,47.04 108.92,47.04 IC12.52 | v99.85,57.48 99.85,58.09 IC12.89 | v103.85,57.48 103.85,58.09 IC12.81 | v108.27,51.54 108.92,51.54 IC12.61 | v107.85,60.26 107.85,59.65 IC12.73 | v23.84,14.92 24.49,14.92 CF1.50 | v23.84,25.74 24.49,25.74 CF1.17 | v23.84,27 CF1.16 | v23.84,32.07 24.49,32.07 CF1.12 | v23.84,33.36 24.49,33.36 CF1.11 | v23.84,34.62 CF1.10 | v23.84,37.17 24.49,37.17 CF1.8 | v23.84,46.05 CF1.1 | v19.34,61.86 19.99,61.86 IC10.7 | v34.16,60.34 34.81,60.34 IC8.10 | v34.16,71.77 34.81,71.77 IC8.1 | v51.73,59.96 52.37,59.96 IC9.10 | v61.79,70.09 62.43,70.09 IC9.19 | IC17.7 v129.95,7.65 | v129.95,17.82 130.59,17.82 IC15.7 | v136.08,14.01 136.73,14.01 IC17.13 | v129.95,20.33 130.59,20.33 IC15.5 | v136.08,19.08 IC15.9 | v136.08,21.63 136.73,21.63 IC15.11 | v126.71,32.41 IC13.10
  Top 0.254: v136.08,24.14 136.73,24.14 IC15.13 | v136.77,42.58 137.41,42.58 IC13.19 | v120.65,60.11 121.3,60.11 IC11.8 | v9.32,72.3 9.32,72.95 C8.2 | v61.67,34.39 61.67,35.04 C17.2 | v29.55,71.35 30.2,71.35 C13.2 | v24.9,79.39 25.55,79.39 IC2.16 | v28.37,74.85 28.37,75.5 C5.2 | v48.18,66.93 48.83,66.93 C14.2 | v43.95,79.39 44.6,79.39 IC3.16 | v125.11,15.61 125.11,15 IC16.4 | v63,79.39 63.65,79.39 IC4.16 | v69.86,74.97 69.86,75.62 C6.2 | v93.26,66.55 IC7.8 | v83.35,79.39 84,79.39 IC5.16 | v89.87,75.01 90.51,75.01 C9.2 | v108.84,76.76 108.84,77.41 C7.2 | v101.1,84.49 101.75,84.49 REG2.5.2 | v101.1,85.75 REG2.5.1 | v104.91,89.75 104.91,89.14 C3.2 | v109.98,84.49 110.63,84.49 REG3.3.2 | REG3.3.1 v109.98,85.75 | v113.72,86.78 113.72,87.43 C4.2 | v134.06,67.31 134.71,67.31 C10.2 | v110.36,34.62 111.01,34.62 R7.1 | v114.13,67.04 114.13,67.69 X1.P$2 | v134.18,63.31 134.82,63.31 C11.2 | v18.47,57.33 18.47,57.98 R4.2 | v105.45,96.46 105.45,97.1 C1.- | v114.33,96.46 C2.- | v56.26,28.18 56.91,28.18 IC14.4 | v56.26,29.48 56.91,29.48 IC14.3 | IC6.8 v79.35,66.4
  Bottom 0.254: C106.2 113.91,49.59 113.91,48.83 113.87,48.79 113.87,47.96 C102.2 113.87,46.47 v113.87,45.82 | C103.2 84.38,49.75 84.38,48.68 C104.2 84.38,47.19 v84.38,46.55 | C107.2 98.97,63.12 98.55,63.12 98.51,63.16 98.02,63.16 C105.2 96.53,63.16 v95.89,63.16 | C100.2 98.55,33.48 97.6,33.48 C101.2 96.15,33.48 v95.5,33.48
HS  (via drill 0.38)
  Top 0.178: v84.57,53.9 85.37,53.1 87.69,53.1 IC12.117 | v120.31,87.43 121.83,88.95 146.06,88.95 146.9,89.79 149.19,89.79 VGA.13
  Bottom 0.178: v84.57,53.9 84.11,54.36 84.11,64.6 82.09,66.62 82.09,79.04 90.47,87.43 v120.31,87.43
INTGNT_L  (via drill 0.38)
  Top 0.178: v83.92,42.35 83.92,41.44 84.46,40.91 86.66,40.91 86.74,40.98 87.69,40.98 IC12.141 | v81.1,55.42 80.76,55.77 74.36,55.77 SBC.10
  Bottom 0.178: v83.92,42.35 83.31,42.96 83.31,53.21 v81.1,55.42
INTREQ_L  (via drill 0.38)
  Top 0.178: v96.11,60.26 96.27,60.26 96.27,59.65 IC12.96 | v88.19,57.75 87.58,58.36 83.96,58.36 82.51,56.91 72.57,56.91 71.84,56.18 SBC.9
  Route2 0.178: v96.11,60.26 93.14,57.29 93.14,57.25 92.72,56.83 90.97,56.83 90.06,57.75 v88.19,57.75
IOCLR_L  (via drill 0.38)
  Top 0.178: v60.6,99.09 59.27,100.42 12.26,100.42 12.26,98.82 IC1.12 | v100.72,60.26 100.76,60.26 100.76,59.65 IC12.87
  Route2 0.178: v100.72,60.26 99.66,60.26 94.28,54.89 90.78,54.89 90.13,55.54 83.96,55.54 81.83,53.4 74.36,53.4 SBC.12
  Bottom 0.178: v60.6,99.09 60.53,99.01 60.53,96.3 64.34,92.49 70.47,92.49 70.47,82.32 70.74,82.05 70.74,74.43 72.8,72.38 72.8,66.62 72.68,66.51 72.68,54.74 73.37,54.05 SBC.12
KB_CLK  (via drill 0.38)
  Top 0.178: v84.72,41.55 85.64,42.47 87.69,42.47 IC12.138 | v81.52,19 81.71,18.81 114.4,18.81 119.7,24.1 v124.23,24.1
  Bottom 0.178: v84.72,41.55 82.32,39.15 82.32,25.4 81.52,24.6 v81.52,19 | v124.23,24.1 139.24,39.12 139.24,55.23 146.1,62.09 146.1,68.53 146.79,69.22 KBD.6
KB_DATA  (via drill 0.38)
  Top 0.178: v87.12,45.55 87.58,45.1 87.69,45.1 IC12.133
  Bottom 0.178: v87.12,45.55 87.69,46.13 87.69,52.3 86.74,53.25 83.73,53.25 83.73,63.88 81.71,65.9 81.71,79.2 100.76,98.25 133.53,98.25 133.53,94.28 137.57,90.25 143.81,90.25 143.81,74.59 148.96,69.44 148.96,68.8 149.68,68.07 KBD.1
LOAD_DAR_H  (via drill 0.38)
  Top 0.178: v47.46,59.92 46.96,59.92 46.85,60.03 IC8.11 | v49.14,49.21 49.75,48.6 70.47,48.6 SBC.15
  Bottom 0.178: v47.46,59.92 49.14,58.24 v49.14,49.21
LXDAR_L  (via drill 0.38)
  Top 0.178: v72.45,41.21 72.45,39.08 72.53,39 72.53,37.86 73.25,37.13 73.56,37.13 75.39,35.31 78.78,35.31 79.65,34.43 98.78,34.43 98.78,36.91 IC12.18
  Bottom 0.178: v72.45,41.21 72.68,41.44 72.68,49.4 73.41,50.13 SBC.14
MA0  (via drill 0.38)
  Top 0.178: v15.27,95.89 15.27,97.26 IC1.6 | v20.71,90.44 21.02,90.13 37.82,90.13 38.13,89.83 38.35,89.83 IC2.25 40.53,89.83 40.56,89.87 44.22,89.87 44.49,90.13 55.54,90.13 v55.8,89.9 56.07,89.64 56.6,89.64 56.68,89.56 IC3.25 59.58,89.83 59.61,89.87 62.51,89.87 62.81,90.17 66.13,90.17 66.51,89.79 76.45,89.79 IC4.25 78.63,89.79 78.82,89.79 79.16,90.13 96.49,90.13 96.8,89.83 IC5.25 | v63,40.94 69.48,34.47 72.15,34.47 72.15,32.41 73.37,31.19 SBC.30
  Bottom 0.178: v20.71,90.44 v15.27,95.89 | v63,40.94 61.02,42.93 61.02,46.13 59.46,47.69 59.46,88.61 57.21,90.86 55.8,90.86 v55.8,89.9
MA1  (via drill 0.38)
  Top 0.178: v28.37,99.09 27.42,100.04 14.77,100.04 14.77,98.82 IC1.7 | v32.41,87.12 38.35,87.12 IC2.23 40.53,87.27 41.21,87.27 41.55,87.62 46.89,87.62 47.19,87.31 57.37,87.31 57.4,87.27 IC3.23 59.58,87.27 59.61,87.31 63.23,87.31 63.35,87.43 63.39,87.43 63.39,87.46 63.42,87.46 63.42,87.5 63.46,87.5 63.46,87.54 63.5,87.54 63.5,87.58 63.54,87.58 63.54,87.62 65.94,87.62 66.28,87.27 76.45,87.27 IC4.23 78.63,87.27 78.66,87.31 80.72,87.31 | 80.72,87.31 83.58,87.31 83.88,87.62 96.49,87.62 96.8,87.31 IC5.23 | v78.36,31.38 75.54,28.56 74.63,28.56 74.36,28.3 SBC.32 | v80.72,87.08 80.72,87.31
  Bottom 0.178: v28.37,99.09 29.36,98.09 32.41,98.09 v32.41,87.12 | v78.36,31.38 80.15,33.17 80.15,60.03 80.72,60.6 v80.72,87.08
MA2  (via drill 0.38)
  Top 0.178: v28.22,94.06 14.27,94.06 14.27,97.26 IC1.8 | v30.81,91.47 31.19,91.08 38.35,91.08 IC2.26 40.53,91.08 41.06,91.08 41.4,91.43 46.89,91.43 47.19,91.12 57.37,91.12 57.4,91.08 IC3.26 59.58,91.08 61.82,91.08 62.17,91.43 65.94,91.43 66.24,91.12 68.26,91.12 | 68.26,91.12 76.42,91.12 76.45,91.08 IC4.26 78.63,91.08 78.85,91.08 79.2,91.43 96.49,91.43 96.8,91.12 IC5.26 | v68.38,37.63 69.06,36.94 72.15,36.94 72.15,35 73.41,33.74 SBC.28 | v68.26,90.82 68.26,91.12
  Bottom 0.178: v30.81,91.47 v28.22,94.06 | v68.38,37.63 68.26,37.74 v68.26,90.82
MA3  (via drill 0.38)
  Top 0.178: v9.44,96.65 9.28,96.65 9.28,97.26 IC1.18 | v11.84,93.94 13.06,92.72 37.78,92.72 38.16,92.34 38.35,92.34 IC2.27 40.53,92.38 41.29,92.38 41.59,92.68 46.89,92.68 47.16,92.42 57.33,92.42 57.4,92.34 IC3.27 59.58,92.11 61.02,92.11 61.6,92.68 62.36,92.68 | 62.36,92.68 65.94,92.68 66.21,92.42 76.38,92.42 76.45,92.34 IC4.27 78.63,92.38 78.89,92.38 79.2,92.68 96.49,92.68 96.8,92.38 IC5.27 | v63,47.23 70.55,39.69 71.01,39.69 71.84,38.85 72.15,38.85 72.15,37.48 73.37,36.26 SBC.26 | 62.36,92.68 v62.36,92.46
  Bottom 0.178: v9.44,96.65 11.84,94.25 v11.84,93.94 | v63,47.23 62.43,47.8 62.43,79.04 62.36,79.12 v62.36,92.46
MA4  (via drill 0.38)
  Top 0.178: IC1.19 8.79,97.26 8.79,94.59 13.17,94.59 14.12,93.64 25.55,93.64 IC2.5 27.72,93.1 37.94,93.1 38.24,92.8 41.17,92.8 41.48,93.1 44.6,93.1 IC3.5 46.77,93.1 46.81,93.07 57.02,93.07 57.29,92.8 60.03,92.8 | 60.03,92.8 61.18,92.8 61.48,93.1 63.65,93.1 IC4.5 65.82,93.1 67.81,93.1 68.11,92.8 78.78,92.8 79.04,93.07 83.96,93.07 84,93.1 IC5.5 | v63,44.68 64.22,44.68 70.47,38.43 SBC.23 | 60.03,92.8 v60.03,92.76
  Bottom 0.178: v63,44.68 59.84,47.84 59.84,92.57 v60.03,92.76
MA5  (via drill 0.38)
  Top 0.178: IC1.20 8.14,98.82 8.14,100.04 6.88,100.04 5.63,98.78 5.63,92.34 25.55,92.34 IC2.6 27.72,92.11 37.55,92.11 38.16,91.5 40.94,91.5 41.29,91.85 44.6,91.85 IC3.6 46.77,91.85 46.81,91.81 56.98,91.81 57.29,91.5 61.71,91.5 62.01,91.81 63.69,91.81 IC4.6 65.82,91.85 66.05,91.85 66.4,91.5 67.61,91.5 | 67.61,91.5 78.74,91.5 79.04,91.81 84,91.81 IC5.6 | v68.38,36.49 69.9,36.49 70.47,35.92 SBC.25 | 67.61,91.5 v67.61,91.77
  Bottom 0.178: v68.38,36.49 67.61,37.25 v67.61,91.77
MA6  (via drill 0.38)
  Top 0.178: v7.76,96.65 7.76,97.26 IC1.21 | v10.96,91.69 11.57,91.08 25.55,91.08 IC2.7 27.72,90.55 27.76,90.51 37.97,90.51 38.24,90.25 44.07,90.25 44.41,90.59 44.6,90.59 IC3.7 46.77,90.55 56.98,90.55 57.16,90.38 | 57.16,90.38 57.29,90.25 62.36,90.25 62.7,90.59 63.65,90.59 IC4.7 65.82,90.55 66.28,90.55 66.66,90.17 78.66,90.17 79.01,90.51 83.96,90.51 84,90.55 IC5.7 | v63,39.12 68.07,34.05 69.79,34.05 70.47,33.36 SBC.27 | v56.95,90.21 57.06,90.32 57.1,90.32 57.16,90.38
  Bottom 0.178: v7.76,96.65 8.98,95.43 8.98,93.68 v10.96,91.69 | v63,39.12 60.64,41.48 60.64,45.97 58.36,48.26 58.36,68.49 57.59,69.25 57.59,89.56 v56.95,90.21
MA7  (via drill 0.38)
  Top 0.178: v7.26,99.39 7.26,98.82 IC1.22 | v19.53,90.44 20.22,89.75 25.55,89.75 IC2.8 27.72,89.37 37.86,89.37 38.24,88.99 44.07,88.99 44.37,89.29 44.6,89.29 IC3.8 46.77,89.29 46.81,89.26 56.45,89.26 56.72,88.99 59.73,88.99 60.03,89.29 63.08,89.29 | 63.08,89.29 63.65,89.29 IC4.8 65.82,89.29 66.05,89.29 66.36,88.99 78.78,88.99 79.04,89.26 83.96,89.26 84,89.29 IC5.8 | v65.82,33.4 67.88,33.4 70.47,30.81 SBC.29 | v63.08,89.52 63.08,89.29
  Bottom 0.178: v7.26,99.39 9.32,97.33 14.62,97.33 14.62,95.35 v19.53,90.44 | v65.82,33.4 65.71,33.52 65.71,68.99 64.03,70.66 64.03,88.57 v63.08,89.52
MA8  (via drill 0.38)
